VERSION 5.8 ;
BUSBITCHARS "[]" ;
DIVIDERCHAR "/" ;
UNITS
    DATABASE MICRONS 1000 ;
END UNITS

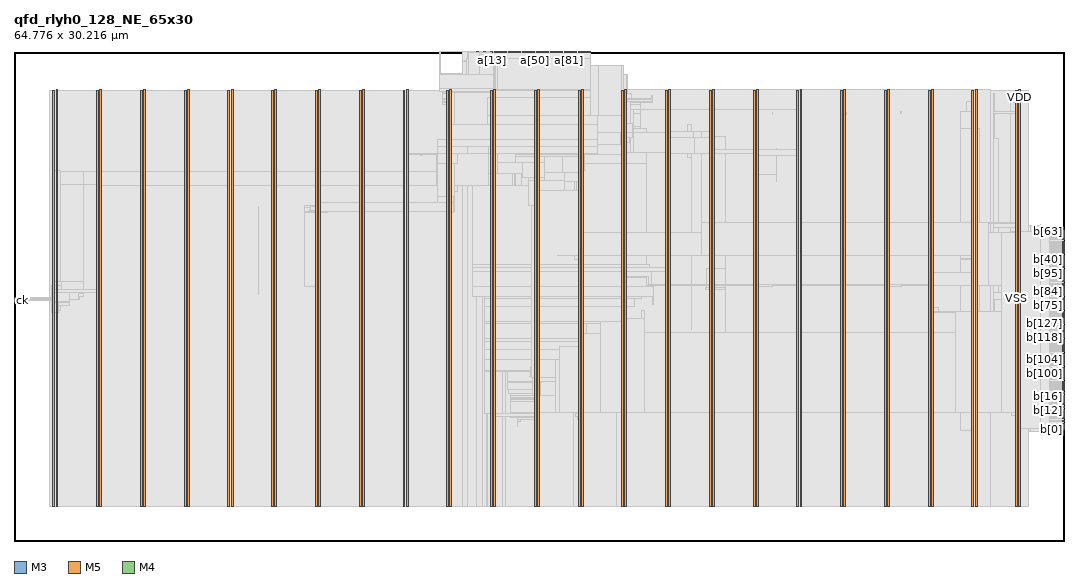
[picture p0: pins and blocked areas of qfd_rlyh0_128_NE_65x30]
MACRO qfd_rlyh0_128_NE_65x30
  FOREIGN qfd_rlyh0_128_NE_65x30 0 0 ;
  CLASS BLOCK ;
  SIZE 64.776 BY 30.216 ;
  PIN a[0]
    DIRECTION INPUT ;
    USE SIGNAL ;
    PORT
      LAYER M3 ;
        RECT  28.548 30.179 28.566 30.216 ;
    END
  END a[0]
  PIN a[100]
    DIRECTION INPUT ;
    USE SIGNAL ;
    PORT
      LAYER M5 ;
        RECT  29.904 30.132 29.928 30.216 ;
    END
  END a[100]
  PIN a[101]
    DIRECTION INPUT ;
    USE SIGNAL ;
    PORT
      LAYER M5 ;
        RECT  30 30.132 30.024 30.216 ;
    END
  END a[101]
  PIN a[102]
    DIRECTION INPUT ;
    USE SIGNAL ;
    PORT
      LAYER M5 ;
        RECT  30.096 30.132 30.12 30.216 ;
    END
  END a[102]
  PIN a[103]
    DIRECTION INPUT ;
    USE SIGNAL ;
    PORT
      LAYER M5 ;
        RECT  30.192 30.132 30.216 30.216 ;
    END
  END a[103]
  PIN a[104]
    DIRECTION INPUT ;
    USE SIGNAL ;
    PORT
      LAYER M5 ;
        RECT  30.288 30.132 30.312 30.216 ;
    END
  END a[104]
  PIN a[105]
    DIRECTION INPUT ;
    USE SIGNAL ;
    PORT
      LAYER M5 ;
        RECT  30.384 30.132 30.408 30.216 ;
    END
  END a[105]
  PIN a[106]
    DIRECTION INPUT ;
    USE SIGNAL ;
    PORT
      LAYER M5 ;
        RECT  30.48 30.132 30.504 30.216 ;
    END
  END a[106]
  PIN a[107]
    DIRECTION INPUT ;
    USE SIGNAL ;
    PORT
      LAYER M5 ;
        RECT  30.576 30.132 30.6 30.216 ;
    END
  END a[107]
  PIN a[108]
    DIRECTION INPUT ;
    USE SIGNAL ;
    PORT
      LAYER M5 ;
        RECT  30.672 30.132 30.696 30.216 ;
    END
  END a[108]
  PIN a[109]
    DIRECTION INPUT ;
    USE SIGNAL ;
    PORT
      LAYER M5 ;
        RECT  30.768 30.132 30.792 30.216 ;
    END
  END a[109]
  PIN a[10]
    DIRECTION INPUT ;
    USE SIGNAL ;
    PORT
      LAYER M3 ;
        RECT  29.268 30.179 29.286 30.216 ;
    END
  END a[10]
  PIN a[110]
    DIRECTION INPUT ;
    USE SIGNAL ;
    PORT
      LAYER M5 ;
        RECT  30.864 30.132 30.888 30.216 ;
    END
  END a[110]
  PIN a[111]
    DIRECTION INPUT ;
    USE SIGNAL ;
    PORT
      LAYER M5 ;
        RECT  30.96 30.132 30.984 30.216 ;
    END
  END a[111]
  PIN a[112]
    DIRECTION INPUT ;
    USE SIGNAL ;
    PORT
      LAYER M5 ;
        RECT  31.056 30.132 31.08 30.216 ;
    END
  END a[112]
  PIN a[113]
    DIRECTION INPUT ;
    USE SIGNAL ;
    PORT
      LAYER M5 ;
        RECT  31.152 30.132 31.176 30.216 ;
    END
  END a[113]
  PIN a[114]
    DIRECTION INPUT ;
    USE SIGNAL ;
    PORT
      LAYER M5 ;
        RECT  31.248 30.132 31.272 30.216 ;
    END
  END a[114]
  PIN a[115]
    DIRECTION INPUT ;
    USE SIGNAL ;
    PORT
      LAYER M5 ;
        RECT  31.344 30.132 31.368 30.216 ;
    END
  END a[115]
  PIN a[116]
    DIRECTION INPUT ;
    USE SIGNAL ;
    PORT
      LAYER M5 ;
        RECT  31.44 30.132 31.464 30.216 ;
    END
  END a[116]
  PIN a[117]
    DIRECTION INPUT ;
    USE SIGNAL ;
    PORT
      LAYER M5 ;
        RECT  31.536 30.132 31.56 30.216 ;
    END
  END a[117]
  PIN a[118]
    DIRECTION INPUT ;
    USE SIGNAL ;
    PORT
      LAYER M5 ;
        RECT  31.632 30.132 31.656 30.216 ;
    END
  END a[118]
  PIN a[119]
    DIRECTION INPUT ;
    USE SIGNAL ;
    PORT
      LAYER M5 ;
        RECT  31.728 30.132 31.752 30.216 ;
    END
  END a[119]
  PIN a[11]
    DIRECTION INPUT ;
    USE SIGNAL ;
    PORT
      LAYER M3 ;
        RECT  29.34 30.179 29.358 30.216 ;
    END
  END a[11]
  PIN a[120]
    DIRECTION INPUT ;
    USE SIGNAL ;
    PORT
      LAYER M5 ;
        RECT  31.824 30.132 31.848 30.216 ;
    END
  END a[120]
  PIN a[121]
    DIRECTION INPUT ;
    USE SIGNAL ;
    PORT
      LAYER M5 ;
        RECT  31.92 30.132 31.944 30.216 ;
    END
  END a[121]
  PIN a[122]
    DIRECTION INPUT ;
    USE SIGNAL ;
    PORT
      LAYER M5 ;
        RECT  32.016 30.132 32.04 30.216 ;
    END
  END a[122]
  PIN a[123]
    DIRECTION INPUT ;
    USE SIGNAL ;
    PORT
      LAYER M5 ;
        RECT  32.112 30.132 32.136 30.216 ;
    END
  END a[123]
  PIN a[124]
    DIRECTION INPUT ;
    USE SIGNAL ;
    PORT
      LAYER M5 ;
        RECT  32.208 30.132 32.232 30.216 ;
    END
  END a[124]
  PIN a[125]
    DIRECTION INPUT ;
    USE SIGNAL ;
    PORT
      LAYER M5 ;
        RECT  32.304 30.132 32.328 30.216 ;
    END
  END a[125]
  PIN a[126]
    DIRECTION INPUT ;
    USE SIGNAL ;
    PORT
      LAYER M5 ;
        RECT  32.4 30.132 32.424 30.216 ;
    END
  END a[126]
  PIN a[127]
    DIRECTION INPUT ;
    USE SIGNAL ;
    PORT
      LAYER M5 ;
        RECT  32.496 30.132 32.52 30.216 ;
    END
  END a[127]
  PIN a[12]
    DIRECTION INPUT ;
    USE SIGNAL ;
    PORT
      LAYER M3 ;
        RECT  29.412 30.179 29.43 30.216 ;
    END
  END a[12]
  PIN a[13]
    DIRECTION INPUT ;
    USE SIGNAL ;
    PORT
      LAYER M3 ;
        RECT  29.484 30.179 29.502 30.216 ;
    END
  END a[13]
  PIN a[14]
    DIRECTION INPUT ;
    USE SIGNAL ;
    PORT
      LAYER M3 ;
        RECT  29.556 30.179 29.574 30.216 ;
    END
  END a[14]
  PIN a[15]
    DIRECTION INPUT ;
    USE SIGNAL ;
    PORT
      LAYER M3 ;
        RECT  29.628 30.179 29.646 30.216 ;
    END
  END a[15]
  PIN a[16]
    DIRECTION INPUT ;
    USE SIGNAL ;
    PORT
      LAYER M3 ;
        RECT  29.7 30.179 29.718 30.216 ;
    END
  END a[16]
  PIN a[17]
    DIRECTION INPUT ;
    USE SIGNAL ;
    PORT
      LAYER M3 ;
        RECT  29.772 30.179 29.79 30.216 ;
    END
  END a[17]
  PIN a[18]
    DIRECTION INPUT ;
    USE SIGNAL ;
    PORT
      LAYER M3 ;
        RECT  29.844 30.179 29.862 30.216 ;
    END
  END a[18]
  PIN a[19]
    DIRECTION INPUT ;
    USE SIGNAL ;
    PORT
      LAYER M3 ;
        RECT  29.916 30.179 29.934 30.216 ;
    END
  END a[19]
  PIN a[1]
    DIRECTION INPUT ;
    USE SIGNAL ;
    PORT
      LAYER M3 ;
        RECT  28.62 30.179 28.638 30.216 ;
    END
  END a[1]
  PIN a[20]
    DIRECTION INPUT ;
    USE SIGNAL ;
    PORT
      LAYER M3 ;
        RECT  29.988 30.179 30.006 30.216 ;
    END
  END a[20]
  PIN a[21]
    DIRECTION INPUT ;
    USE SIGNAL ;
    PORT
      LAYER M3 ;
        RECT  30.06 30.179 30.078 30.216 ;
    END
  END a[21]
  PIN a[22]
    DIRECTION INPUT ;
    USE SIGNAL ;
    PORT
      LAYER M3 ;
        RECT  30.132 30.179 30.15 30.216 ;
    END
  END a[22]
  PIN a[23]
    DIRECTION INPUT ;
    USE SIGNAL ;
    PORT
      LAYER M3 ;
        RECT  30.204 30.179 30.222 30.216 ;
    END
  END a[23]
  PIN a[24]
    DIRECTION INPUT ;
    USE SIGNAL ;
    PORT
      LAYER M3 ;
        RECT  30.276 30.179 30.294 30.216 ;
    END
  END a[24]
  PIN a[25]
    DIRECTION INPUT ;
    USE SIGNAL ;
    PORT
      LAYER M3 ;
        RECT  30.348 30.179 30.366 30.216 ;
    END
  END a[25]
  PIN a[26]
    DIRECTION INPUT ;
    USE SIGNAL ;
    PORT
      LAYER M3 ;
        RECT  30.42 30.179 30.438 30.216 ;
    END
  END a[26]
  PIN a[27]
    DIRECTION INPUT ;
    USE SIGNAL ;
    PORT
      LAYER M3 ;
        RECT  30.492 30.179 30.51 30.216 ;
    END
  END a[27]
  PIN a[28]
    DIRECTION INPUT ;
    USE SIGNAL ;
    PORT
      LAYER M3 ;
        RECT  30.564 30.179 30.582 30.216 ;
    END
  END a[28]
  PIN a[29]
    DIRECTION INPUT ;
    USE SIGNAL ;
    PORT
      LAYER M3 ;
        RECT  30.636 30.179 30.654 30.216 ;
    END
  END a[29]
  PIN a[2]
    DIRECTION INPUT ;
    USE SIGNAL ;
    PORT
      LAYER M3 ;
        RECT  28.692 30.179 28.71 30.216 ;
    END
  END a[2]
  PIN a[30]
    DIRECTION INPUT ;
    USE SIGNAL ;
    PORT
      LAYER M3 ;
        RECT  30.708 30.179 30.726 30.216 ;
    END
  END a[30]
  PIN a[31]
    DIRECTION INPUT ;
    USE SIGNAL ;
    PORT
      LAYER M3 ;
        RECT  30.78 30.179 30.798 30.216 ;
    END
  END a[31]
  PIN a[32]
    DIRECTION INPUT ;
    USE SIGNAL ;
    PORT
      LAYER M3 ;
        RECT  30.852 30.179 30.87 30.216 ;
    END
  END a[32]
  PIN a[33]
    DIRECTION INPUT ;
    USE SIGNAL ;
    PORT
      LAYER M3 ;
        RECT  30.924 30.179 30.942 30.216 ;
    END
  END a[33]
  PIN a[34]
    DIRECTION INPUT ;
    USE SIGNAL ;
    PORT
      LAYER M3 ;
        RECT  30.996 30.179 31.014 30.216 ;
    END
  END a[34]
  PIN a[35]
    DIRECTION INPUT ;
    USE SIGNAL ;
    PORT
      LAYER M3 ;
        RECT  31.068 30.179 31.086 30.216 ;
    END
  END a[35]
  PIN a[36]
    DIRECTION INPUT ;
    USE SIGNAL ;
    PORT
      LAYER M3 ;
        RECT  31.14 30.179 31.158 30.216 ;
    END
  END a[36]
  PIN a[37]
    DIRECTION INPUT ;
    USE SIGNAL ;
    PORT
      LAYER M3 ;
        RECT  31.212 30.179 31.23 30.216 ;
    END
  END a[37]
  PIN a[38]
    DIRECTION INPUT ;
    USE SIGNAL ;
    PORT
      LAYER M3 ;
        RECT  31.284 30.179 31.302 30.216 ;
    END
  END a[38]
  PIN a[39]
    DIRECTION INPUT ;
    USE SIGNAL ;
    PORT
      LAYER M3 ;
        RECT  31.356 30.179 31.374 30.216 ;
    END
  END a[39]
  PIN a[3]
    DIRECTION INPUT ;
    USE SIGNAL ;
    PORT
      LAYER M3 ;
        RECT  28.764 30.179 28.782 30.216 ;
    END
  END a[3]
  PIN a[40]
    DIRECTION INPUT ;
    USE SIGNAL ;
    PORT
      LAYER M3 ;
        RECT  31.428 30.179 31.446 30.216 ;
    END
  END a[40]
  PIN a[41]
    DIRECTION INPUT ;
    USE SIGNAL ;
    PORT
      LAYER M3 ;
        RECT  31.5 30.179 31.518 30.216 ;
    END
  END a[41]
  PIN a[42]
    DIRECTION INPUT ;
    USE SIGNAL ;
    PORT
      LAYER M3 ;
        RECT  31.572 30.179 31.59 30.216 ;
    END
  END a[42]
  PIN a[43]
    DIRECTION INPUT ;
    USE SIGNAL ;
    PORT
      LAYER M3 ;
        RECT  31.644 30.179 31.662 30.216 ;
    END
  END a[43]
  PIN a[44]
    DIRECTION INPUT ;
    USE SIGNAL ;
    PORT
      LAYER M3 ;
        RECT  31.716 30.179 31.734 30.216 ;
    END
  END a[44]
  PIN a[45]
    DIRECTION INPUT ;
    USE SIGNAL ;
    PORT
      LAYER M3 ;
        RECT  31.788 30.179 31.806 30.216 ;
    END
  END a[45]
  PIN a[46]
    DIRECTION INPUT ;
    USE SIGNAL ;
    PORT
      LAYER M3 ;
        RECT  31.86 30.179 31.878 30.216 ;
    END
  END a[46]
  PIN a[47]
    DIRECTION INPUT ;
    USE SIGNAL ;
    PORT
      LAYER M3 ;
        RECT  31.932 30.179 31.95 30.216 ;
    END
  END a[47]
  PIN a[48]
    DIRECTION INPUT ;
    USE SIGNAL ;
    PORT
      LAYER M3 ;
        RECT  32.004 30.179 32.022 30.216 ;
    END
  END a[48]
  PIN a[49]
    DIRECTION INPUT ;
    USE SIGNAL ;
    PORT
      LAYER M3 ;
        RECT  32.076 30.179 32.094 30.216 ;
    END
  END a[49]
  PIN a[4]
    DIRECTION INPUT ;
    USE SIGNAL ;
    PORT
      LAYER M3 ;
        RECT  28.836 30.179 28.854 30.216 ;
    END
  END a[4]
  PIN a[50]
    DIRECTION INPUT ;
    USE SIGNAL ;
    PORT
      LAYER M3 ;
        RECT  32.148 30.179 32.166 30.216 ;
    END
  END a[50]
  PIN a[51]
    DIRECTION INPUT ;
    USE SIGNAL ;
    PORT
      LAYER M3 ;
        RECT  32.22 30.179 32.238 30.216 ;
    END
  END a[51]
  PIN a[52]
    DIRECTION INPUT ;
    USE SIGNAL ;
    PORT
      LAYER M3 ;
        RECT  32.292 30.179 32.31 30.216 ;
    END
  END a[52]
  PIN a[53]
    DIRECTION INPUT ;
    USE SIGNAL ;
    PORT
      LAYER M3 ;
        RECT  32.364 30.179 32.382 30.216 ;
    END
  END a[53]
  PIN a[54]
    DIRECTION INPUT ;
    USE SIGNAL ;
    PORT
      LAYER M3 ;
        RECT  32.436 30.179 32.454 30.216 ;
    END
  END a[54]
  PIN a[55]
    DIRECTION INPUT ;
    USE SIGNAL ;
    PORT
      LAYER M3 ;
        RECT  32.508 30.179 32.526 30.216 ;
    END
  END a[55]
  PIN a[56]
    DIRECTION INPUT ;
    USE SIGNAL ;
    PORT
      LAYER M3 ;
        RECT  32.58 30.179 32.598 30.216 ;
    END
  END a[56]
  PIN a[57]
    DIRECTION INPUT ;
    USE SIGNAL ;
    PORT
      LAYER M3 ;
        RECT  32.652 30.179 32.67 30.216 ;
    END
  END a[57]
  PIN a[58]
    DIRECTION INPUT ;
    USE SIGNAL ;
    PORT
      LAYER M3 ;
        RECT  32.724 30.179 32.742 30.216 ;
    END
  END a[58]
  PIN a[59]
    DIRECTION INPUT ;
    USE SIGNAL ;
    PORT
      LAYER M3 ;
        RECT  32.796 30.179 32.814 30.216 ;
    END
  END a[59]
  PIN a[5]
    DIRECTION INPUT ;
    USE SIGNAL ;
    PORT
      LAYER M3 ;
        RECT  28.908 30.179 28.926 30.216 ;
    END
  END a[5]
  PIN a[60]
    DIRECTION INPUT ;
    USE SIGNAL ;
    PORT
      LAYER M3 ;
        RECT  32.868 30.179 32.886 30.216 ;
    END
  END a[60]
  PIN a[61]
    DIRECTION INPUT ;
    USE SIGNAL ;
    PORT
      LAYER M3 ;
        RECT  32.94 30.179 32.958 30.216 ;
    END
  END a[61]
  PIN a[62]
    DIRECTION INPUT ;
    USE SIGNAL ;
    PORT
      LAYER M3 ;
        RECT  33.012 30.179 33.03 30.216 ;
    END
  END a[62]
  PIN a[63]
    DIRECTION INPUT ;
    USE SIGNAL ;
    PORT
      LAYER M3 ;
        RECT  33.084 30.179 33.102 30.216 ;
    END
  END a[63]
  PIN a[64]
    DIRECTION INPUT ;
    USE SIGNAL ;
    PORT
      LAYER M5 ;
        RECT  32.592 30.132 32.616 30.216 ;
    END
  END a[64]
  PIN a[65]
    DIRECTION INPUT ;
    USE SIGNAL ;
    PORT
      LAYER M5 ;
        RECT  32.688 30.132 32.712 30.216 ;
    END
  END a[65]
  PIN a[66]
    DIRECTION INPUT ;
    USE SIGNAL ;
    PORT
      LAYER M5 ;
        RECT  32.784 30.132 32.808 30.216 ;
    END
  END a[66]
  PIN a[67]
    DIRECTION INPUT ;
    USE SIGNAL ;
    PORT
      LAYER M5 ;
        RECT  32.88 30.132 32.904 30.216 ;
    END
  END a[67]
  PIN a[68]
    DIRECTION INPUT ;
    USE SIGNAL ;
    PORT
      LAYER M5 ;
        RECT  32.976 30.132 33 30.216 ;
    END
  END a[68]
  PIN a[69]
    DIRECTION INPUT ;
    USE SIGNAL ;
    PORT
      LAYER M5 ;
        RECT  33.072 30.132 33.096 30.216 ;
    END
  END a[69]
  PIN a[6]
    DIRECTION INPUT ;
    USE SIGNAL ;
    PORT
      LAYER M3 ;
        RECT  28.98 30.179 28.998 30.216 ;
    END
  END a[6]
  PIN a[70]
    DIRECTION INPUT ;
    USE SIGNAL ;
    PORT
      LAYER M5 ;
        RECT  33.168 30.132 33.192 30.216 ;
    END
  END a[70]
  PIN a[71]
    DIRECTION INPUT ;
    USE SIGNAL ;
    PORT
      LAYER M5 ;
        RECT  33.264 30.132 33.288 30.216 ;
    END
  END a[71]
  PIN a[72]
    DIRECTION INPUT ;
    USE SIGNAL ;
    PORT
      LAYER M5 ;
        RECT  33.36 30.132 33.384 30.216 ;
    END
  END a[72]
  PIN a[73]
    DIRECTION INPUT ;
    USE SIGNAL ;
    PORT
      LAYER M5 ;
        RECT  33.456 30.132 33.48 30.216 ;
    END
  END a[73]
  PIN a[74]
    DIRECTION INPUT ;
    USE SIGNAL ;
    PORT
      LAYER M5 ;
        RECT  33.552 30.132 33.576 30.216 ;
    END
  END a[74]
  PIN a[75]
    DIRECTION INPUT ;
    USE SIGNAL ;
    PORT
      LAYER M5 ;
        RECT  33.648 30.132 33.672 30.216 ;
    END
  END a[75]
  PIN a[76]
    DIRECTION INPUT ;
    USE SIGNAL ;
    PORT
      LAYER M5 ;
        RECT  33.744 30.132 33.768 30.216 ;
    END
  END a[76]
  PIN a[77]
    DIRECTION INPUT ;
    USE SIGNAL ;
    PORT
      LAYER M5 ;
        RECT  33.84 30.132 33.864 30.216 ;
    END
  END a[77]
  PIN a[78]
    DIRECTION INPUT ;
    USE SIGNAL ;
    PORT
      LAYER M5 ;
        RECT  33.936 30.132 33.96 30.216 ;
    END
  END a[78]
  PIN a[79]
    DIRECTION INPUT ;
    USE SIGNAL ;
    PORT
      LAYER M5 ;
        RECT  34.032 30.132 34.056 30.216 ;
    END
  END a[79]
  PIN a[7]
    DIRECTION INPUT ;
    USE SIGNAL ;
    PORT
      LAYER M3 ;
        RECT  29.052 30.179 29.07 30.216 ;
    END
  END a[7]
  PIN a[80]
    DIRECTION INPUT ;
    USE SIGNAL ;
    PORT
      LAYER M5 ;
        RECT  34.128 30.132 34.152 30.216 ;
    END
  END a[80]
  PIN a[81]
    DIRECTION INPUT ;
    USE SIGNAL ;
    PORT
      LAYER M5 ;
        RECT  34.224 30.132 34.248 30.216 ;
    END
  END a[81]
  PIN a[82]
    DIRECTION INPUT ;
    USE SIGNAL ;
    PORT
      LAYER M5 ;
        RECT  34.32 30.132 34.344 30.216 ;
    END
  END a[82]
  PIN a[83]
    DIRECTION INPUT ;
    USE SIGNAL ;
    PORT
      LAYER M5 ;
        RECT  34.416 30.132 34.44 30.216 ;
    END
  END a[83]
  PIN a[84]
    DIRECTION INPUT ;
    USE SIGNAL ;
    PORT
      LAYER M5 ;
        RECT  34.512 30.132 34.536 30.216 ;
    END
  END a[84]
  PIN a[85]
    DIRECTION INPUT ;
    USE SIGNAL ;
    PORT
      LAYER M5 ;
        RECT  34.608 30.132 34.632 30.216 ;
    END
  END a[85]
  PIN a[86]
    DIRECTION INPUT ;
    USE SIGNAL ;
    PORT
      LAYER M5 ;
        RECT  34.704 30.132 34.728 30.216 ;
    END
  END a[86]
  PIN a[87]
    DIRECTION INPUT ;
    USE SIGNAL ;
    PORT
      LAYER M5 ;
        RECT  34.8 30.132 34.824 30.216 ;
    END
  END a[87]
  PIN a[88]
    DIRECTION INPUT ;
    USE SIGNAL ;
    PORT
      LAYER M5 ;
        RECT  34.896 30.132 34.92 30.216 ;
    END
  END a[88]
  PIN a[89]
    DIRECTION INPUT ;
    USE SIGNAL ;
    PORT
      LAYER M5 ;
        RECT  34.992 30.132 35.016 30.216 ;
    END
  END a[89]
  PIN a[8]
    DIRECTION INPUT ;
    USE SIGNAL ;
    PORT
      LAYER M3 ;
        RECT  29.124 30.179 29.142 30.216 ;
    END
  END a[8]
  PIN a[90]
    DIRECTION INPUT ;
    USE SIGNAL ;
    PORT
      LAYER M5 ;
        RECT  35.088 30.132 35.112 30.216 ;
    END
  END a[90]
  PIN a[91]
    DIRECTION INPUT ;
    USE SIGNAL ;
    PORT
      LAYER M5 ;
        RECT  35.184 30.132 35.208 30.216 ;
    END
  END a[91]
  PIN a[92]
    DIRECTION INPUT ;
    USE SIGNAL ;
    PORT
      LAYER M5 ;
        RECT  35.28 30.132 35.304 30.216 ;
    END
  END a[92]
  PIN a[93]
    DIRECTION INPUT ;
    USE SIGNAL ;
    PORT
      LAYER M5 ;
        RECT  35.376 30.132 35.4 30.216 ;
    END
  END a[93]
  PIN a[94]
    DIRECTION INPUT ;
    USE SIGNAL ;
    PORT
      LAYER M5 ;
        RECT  35.472 30.132 35.496 30.216 ;
    END
  END a[94]
  PIN a[95]
    DIRECTION INPUT ;
    USE SIGNAL ;
    PORT
      LAYER M5 ;
        RECT  35.568 30.132 35.592 30.216 ;
    END
  END a[95]
  PIN a[96]
    DIRECTION INPUT ;
    USE SIGNAL ;
    PORT
      LAYER M5 ;
        RECT  29.52 30.132 29.544 30.216 ;
    END
  END a[96]
  PIN a[97]
    DIRECTION INPUT ;
    USE SIGNAL ;
    PORT
      LAYER M5 ;
        RECT  29.616 30.132 29.64 30.216 ;
    END
  END a[97]
  PIN a[98]
    DIRECTION INPUT ;
    USE SIGNAL ;
    PORT
      LAYER M5 ;
        RECT  29.712 30.132 29.736 30.216 ;
    END
  END a[98]
  PIN a[99]
    DIRECTION INPUT ;
    USE SIGNAL ;
    PORT
      LAYER M5 ;
        RECT  29.808 30.132 29.832 30.216 ;
    END
  END a[99]
  PIN a[9]
    DIRECTION INPUT ;
    USE SIGNAL ;
    PORT
      LAYER M3 ;
        RECT  29.196 30.179 29.214 30.216 ;
    END
  END a[9]
  PIN b[0]
    DIRECTION OUTPUT ;
    USE SIGNAL ;
    PORT
      LAYER M4 ;
        RECT  64.692 6.864 64.776 6.888 ;
    END
  END b[0]
  PIN b[100]
    DIRECTION OUTPUT ;
    USE SIGNAL ;
    PORT
      LAYER M4 ;
        RECT  64.692 10.32 64.776 10.344 ;
    END
  END b[100]
  PIN b[101]
    DIRECTION OUTPUT ;
    USE SIGNAL ;
    PORT
      LAYER M4 ;
        RECT  64.692 10.416 64.776 10.44 ;
    END
  END b[101]
  PIN b[102]
    DIRECTION OUTPUT ;
    USE SIGNAL ;
    PORT
      LAYER M4 ;
        RECT  64.692 10.512 64.776 10.536 ;
    END
  END b[102]
  PIN b[103]
    DIRECTION OUTPUT ;
    USE SIGNAL ;
    PORT
      LAYER M4 ;
        RECT  64.692 10.608 64.776 10.632 ;
    END
  END b[103]
  PIN b[104]
    DIRECTION OUTPUT ;
    USE SIGNAL ;
    PORT
      LAYER M4 ;
        RECT  64.692 10.704 64.776 10.728 ;
    END
  END b[104]
  PIN b[105]
    DIRECTION OUTPUT ;
    USE SIGNAL ;
    PORT
      LAYER M4 ;
        RECT  64.692 10.8 64.776 10.824 ;
    END
  END b[105]
  PIN b[106]
    DIRECTION OUTPUT ;
    USE SIGNAL ;
    PORT
      LAYER M4 ;
        RECT  64.692 10.896 64.776 10.92 ;
    END
  END b[106]
  PIN b[107]
    DIRECTION OUTPUT ;
    USE SIGNAL ;
    PORT
      LAYER M4 ;
        RECT  64.692 10.992 64.776 11.016 ;
    END
  END b[107]
  PIN b[108]
    DIRECTION OUTPUT ;
    USE SIGNAL ;
    PORT
      LAYER M4 ;
        RECT  64.692 11.088 64.776 11.112 ;
    END
  END b[108]
  PIN b[109]
    DIRECTION OUTPUT ;
    USE SIGNAL ;
    PORT
      LAYER M4 ;
        RECT  64.692 11.184 64.776 11.208 ;
    END
  END b[109]
  PIN b[10]
    DIRECTION OUTPUT ;
    USE SIGNAL ;
    PORT
      LAYER M4 ;
        RECT  64.692 7.824 64.776 7.848 ;
    END
  END b[10]
  PIN b[110]
    DIRECTION OUTPUT ;
    USE SIGNAL ;
    PORT
      LAYER M4 ;
        RECT  64.692 11.28 64.776 11.304 ;
    END
  END b[110]
  PIN b[111]
    DIRECTION OUTPUT ;
    USE SIGNAL ;
    PORT
      LAYER M4 ;
        RECT  64.692 11.376 64.776 11.4 ;
    END
  END b[111]
  PIN b[112]
    DIRECTION OUTPUT ;
    USE SIGNAL ;
    PORT
      LAYER M4 ;
        RECT  64.692 11.472 64.776 11.496 ;
    END
  END b[112]
  PIN b[113]
    DIRECTION OUTPUT ;
    USE SIGNAL ;
    PORT
      LAYER M4 ;
        RECT  64.692 11.568 64.776 11.592 ;
    END
  END b[113]
  PIN b[114]
    DIRECTION OUTPUT ;
    USE SIGNAL ;
    PORT
      LAYER M4 ;
        RECT  64.692 11.664 64.776 11.688 ;
    END
  END b[114]
  PIN b[115]
    DIRECTION OUTPUT ;
    USE SIGNAL ;
    PORT
      LAYER M4 ;
        RECT  64.692 11.76 64.776 11.784 ;
    END
  END b[115]
  PIN b[116]
    DIRECTION OUTPUT ;
    USE SIGNAL ;
    PORT
      LAYER M4 ;
        RECT  64.692 11.856 64.776 11.88 ;
    END
  END b[116]
  PIN b[117]
    DIRECTION OUTPUT ;
    USE SIGNAL ;
    PORT
      LAYER M4 ;
        RECT  64.692 11.952 64.776 11.976 ;
    END
  END b[117]
  PIN b[118]
    DIRECTION OUTPUT ;
    USE SIGNAL ;
    PORT
      LAYER M4 ;
        RECT  64.692 12.048 64.776 12.072 ;
    END
  END b[118]
  PIN b[119]
    DIRECTION OUTPUT ;
    USE SIGNAL ;
    PORT
      LAYER M4 ;
        RECT  64.692 12.144 64.776 12.168 ;
    END
  END b[119]
  PIN b[11]
    DIRECTION OUTPUT ;
    USE SIGNAL ;
    PORT
      LAYER M4 ;
        RECT  64.692 7.92 64.776 7.944 ;
    END
  END b[11]
  PIN b[120]
    DIRECTION OUTPUT ;
    USE SIGNAL ;
    PORT
      LAYER M4 ;
        RECT  64.692 12.24 64.776 12.264 ;
    END
  END b[120]
  PIN b[121]
    DIRECTION OUTPUT ;
    USE SIGNAL ;
    PORT
      LAYER M4 ;
        RECT  64.692 12.336 64.776 12.36 ;
    END
  END b[121]
  PIN b[122]
    DIRECTION OUTPUT ;
    USE SIGNAL ;
    PORT
      LAYER M4 ;
        RECT  64.692 12.432 64.776 12.456 ;
    END
  END b[122]
  PIN b[123]
    DIRECTION OUTPUT ;
    USE SIGNAL ;
    PORT
      LAYER M4 ;
        RECT  64.692 12.528 64.776 12.552 ;
    END
  END b[123]
  PIN b[124]
    DIRECTION OUTPUT ;
    USE SIGNAL ;
    PORT
      LAYER M4 ;
        RECT  64.692 12.624 64.776 12.648 ;
    END
  END b[124]
  PIN b[125]
    DIRECTION OUTPUT ;
    USE SIGNAL ;
    PORT
      LAYER M4 ;
        RECT  64.692 12.72 64.776 12.744 ;
    END
  END b[125]
  PIN b[126]
    DIRECTION OUTPUT ;
    USE SIGNAL ;
    PORT
      LAYER M4 ;
        RECT  64.692 12.816 64.776 12.84 ;
    END
  END b[126]
  PIN b[127]
    DIRECTION OUTPUT ;
    USE SIGNAL ;
    PORT
      LAYER M4 ;
        RECT  64.692 12.912 64.776 12.936 ;
    END
  END b[127]
  PIN b[12]
    DIRECTION OUTPUT ;
    USE SIGNAL ;
    PORT
      LAYER M4 ;
        RECT  64.692 8.016 64.776 8.04 ;
    END
  END b[12]
  PIN b[13]
    DIRECTION OUTPUT ;
    USE SIGNAL ;
    PORT
      LAYER M4 ;
        RECT  64.692 8.112 64.776 8.136 ;
    END
  END b[13]
  PIN b[14]
    DIRECTION OUTPUT ;
    USE SIGNAL ;
    PORT
      LAYER M4 ;
        RECT  64.692 8.208 64.776 8.232 ;
    END
  END b[14]
  PIN b[15]
    DIRECTION OUTPUT ;
    USE SIGNAL ;
    PORT
      LAYER M4 ;
        RECT  64.692 8.304 64.776 8.328 ;
    END
  END b[15]
  PIN b[16]
    DIRECTION OUTPUT ;
    USE SIGNAL ;
    PORT
      LAYER M4 ;
        RECT  64.692 8.4 64.776 8.424 ;
    END
  END b[16]
  PIN b[17]
    DIRECTION OUTPUT ;
    USE SIGNAL ;
    PORT
      LAYER M4 ;
        RECT  64.692 8.496 64.776 8.52 ;
    END
  END b[17]
  PIN b[18]
    DIRECTION OUTPUT ;
    USE SIGNAL ;
    PORT
      LAYER M4 ;
        RECT  64.692 8.592 64.776 8.616 ;
    END
  END b[18]
  PIN b[19]
    DIRECTION OUTPUT ;
    USE SIGNAL ;
    PORT
      LAYER M4 ;
        RECT  64.692 8.688 64.776 8.712 ;
    END
  END b[19]
  PIN b[1]
    DIRECTION OUTPUT ;
    USE SIGNAL ;
    PORT
      LAYER M4 ;
        RECT  64.692 6.96 64.776 6.984 ;
    END
  END b[1]
  PIN b[20]
    DIRECTION OUTPUT ;
    USE SIGNAL ;
    PORT
      LAYER M4 ;
        RECT  64.692 8.784 64.776 8.808 ;
    END
  END b[20]
  PIN b[21]
    DIRECTION OUTPUT ;
    USE SIGNAL ;
    PORT
      LAYER M4 ;
        RECT  64.692 8.88 64.776 8.904 ;
    END
  END b[21]
  PIN b[22]
    DIRECTION OUTPUT ;
    USE SIGNAL ;
    PORT
      LAYER M4 ;
        RECT  64.692 8.976 64.776 9 ;
    END
  END b[22]
  PIN b[23]
    DIRECTION OUTPUT ;
    USE SIGNAL ;
    PORT
      LAYER M4 ;
        RECT  64.692 9.072 64.776 9.096 ;
    END
  END b[23]
  PIN b[24]
    DIRECTION OUTPUT ;
    USE SIGNAL ;
    PORT
      LAYER M4 ;
        RECT  64.692 9.168 64.776 9.192 ;
    END
  END b[24]
  PIN b[25]
    DIRECTION OUTPUT ;
    USE SIGNAL ;
    PORT
      LAYER M4 ;
        RECT  64.692 9.264 64.776 9.288 ;
    END
  END b[25]
  PIN b[26]
    DIRECTION OUTPUT ;
    USE SIGNAL ;
    PORT
      LAYER M4 ;
        RECT  64.692 9.36 64.776 9.384 ;
    END
  END b[26]
  PIN b[27]
    DIRECTION OUTPUT ;
    USE SIGNAL ;
    PORT
      LAYER M4 ;
        RECT  64.692 9.456 64.776 9.48 ;
    END
  END b[27]
  PIN b[28]
    DIRECTION OUTPUT ;
    USE SIGNAL ;
    PORT
      LAYER M4 ;
        RECT  64.692 9.552 64.776 9.576 ;
    END
  END b[28]
  PIN b[29]
    DIRECTION OUTPUT ;
    USE SIGNAL ;
    PORT
      LAYER M4 ;
        RECT  64.692 9.648 64.776 9.672 ;
    END
  END b[29]
  PIN b[2]
    DIRECTION OUTPUT ;
    USE SIGNAL ;
    PORT
      LAYER M4 ;
        RECT  64.692 7.056 64.776 7.08 ;
    END
  END b[2]
  PIN b[30]
    DIRECTION OUTPUT ;
    USE SIGNAL ;
    PORT
      LAYER M4 ;
        RECT  64.692 9.744 64.776 9.768 ;
    END
  END b[30]
  PIN b[31]
    DIRECTION OUTPUT ;
    USE SIGNAL ;
    PORT
      LAYER M4 ;
        RECT  64.692 9.84 64.776 9.864 ;
    END
  END b[31]
  PIN b[32]
    DIRECTION OUTPUT ;
    USE SIGNAL ;
    PORT
      LAYER M4 ;
        RECT  64.692 16.08 64.776 16.104 ;
    END
  END b[32]
  PIN b[33]
    DIRECTION OUTPUT ;
    USE SIGNAL ;
    PORT
      LAYER M4 ;
        RECT  64.692 16.176 64.776 16.2 ;
    END
  END b[33]
  PIN b[34]
    DIRECTION OUTPUT ;
    USE SIGNAL ;
    PORT
      LAYER M4 ;
        RECT  64.692 16.272 64.776 16.296 ;
    END
  END b[34]
  PIN b[35]
    DIRECTION OUTPUT ;
    USE SIGNAL ;
    PORT
      LAYER M4 ;
        RECT  64.692 16.368 64.776 16.392 ;
    END
  END b[35]
  PIN b[36]
    DIRECTION OUTPUT ;
    USE SIGNAL ;
    PORT
      LAYER M4 ;
        RECT  64.692 16.464 64.776 16.488 ;
    END
  END b[36]
  PIN b[37]
    DIRECTION OUTPUT ;
    USE SIGNAL ;
    PORT
      LAYER M4 ;
        RECT  64.692 16.56 64.776 16.584 ;
    END
  END b[37]
  PIN b[38]
    DIRECTION OUTPUT ;
    USE SIGNAL ;
    PORT
      LAYER M4 ;
        RECT  64.692 16.656 64.776 16.68 ;
    END
  END b[38]
  PIN b[39]
    DIRECTION OUTPUT ;
    USE SIGNAL ;
    PORT
      LAYER M4 ;
        RECT  64.692 16.752 64.776 16.776 ;
    END
  END b[39]
  PIN b[3]
    DIRECTION OUTPUT ;
    USE SIGNAL ;
    PORT
      LAYER M4 ;
        RECT  64.692 7.152 64.776 7.176 ;
    END
  END b[3]
  PIN b[40]
    DIRECTION OUTPUT ;
    USE SIGNAL ;
    PORT
      LAYER M4 ;
        RECT  64.692 16.848 64.776 16.872 ;
    END
  END b[40]
  PIN b[41]
    DIRECTION OUTPUT ;
    USE SIGNAL ;
    PORT
      LAYER M4 ;
        RECT  64.692 16.944 64.776 16.968 ;
    END
  END b[41]
  PIN b[42]
    DIRECTION OUTPUT ;
    USE SIGNAL ;
    PORT
      LAYER M4 ;
        RECT  64.692 17.04 64.776 17.064 ;
    END
  END b[42]
  PIN b[43]
    DIRECTION OUTPUT ;
    USE SIGNAL ;
    PORT
      LAYER M4 ;
        RECT  64.692 17.136 64.776 17.16 ;
    END
  END b[43]
  PIN b[44]
    DIRECTION OUTPUT ;
    USE SIGNAL ;
    PORT
      LAYER M4 ;
        RECT  64.692 17.232 64.776 17.256 ;
    END
  END b[44]
  PIN b[45]
    DIRECTION OUTPUT ;
    USE SIGNAL ;
    PORT
      LAYER M4 ;
        RECT  64.692 17.328 64.776 17.352 ;
    END
  END b[45]
  PIN b[46]
    DIRECTION OUTPUT ;
    USE SIGNAL ;
    PORT
      LAYER M4 ;
        RECT  64.692 17.424 64.776 17.448 ;
    END
  END b[46]
  PIN b[47]
    DIRECTION OUTPUT ;
    USE SIGNAL ;
    PORT
      LAYER M4 ;
        RECT  64.692 17.52 64.776 17.544 ;
    END
  END b[47]
  PIN b[48]
    DIRECTION OUTPUT ;
    USE SIGNAL ;
    PORT
      LAYER M4 ;
        RECT  64.692 17.616 64.776 17.64 ;
    END
  END b[48]
  PIN b[49]
    DIRECTION OUTPUT ;
    USE SIGNAL ;
    PORT
      LAYER M4 ;
        RECT  64.692 17.712 64.776 17.736 ;
    END
  END b[49]
  PIN b[4]
    DIRECTION OUTPUT ;
    USE SIGNAL ;
    PORT
      LAYER M4 ;
        RECT  64.692 7.248 64.776 7.272 ;
    END
  END b[4]
  PIN b[50]
    DIRECTION OUTPUT ;
    USE SIGNAL ;
    PORT
      LAYER M4 ;
        RECT  64.692 17.808 64.776 17.832 ;
    END
  END b[50]
  PIN b[51]
    DIRECTION OUTPUT ;
    USE SIGNAL ;
    PORT
      LAYER M4 ;
        RECT  64.692 17.904 64.776 17.928 ;
    END
  END b[51]
  PIN b[52]
    DIRECTION OUTPUT ;
    USE SIGNAL ;
    PORT
      LAYER M4 ;
        RECT  64.692 18 64.776 18.024 ;
    END
  END b[52]
  PIN b[53]
    DIRECTION OUTPUT ;
    USE SIGNAL ;
    PORT
      LAYER M4 ;
        RECT  64.692 18.096 64.776 18.12 ;
    END
  END b[53]
  PIN b[54]
    DIRECTION OUTPUT ;
    USE SIGNAL ;
    PORT
      LAYER M4 ;
        RECT  64.692 18.192 64.776 18.216 ;
    END
  END b[54]
  PIN b[55]
    DIRECTION OUTPUT ;
    USE SIGNAL ;
    PORT
      LAYER M4 ;
        RECT  64.692 18.288 64.776 18.312 ;
    END
  END b[55]
  PIN b[56]
    DIRECTION OUTPUT ;
    USE SIGNAL ;
    PORT
      LAYER M4 ;
        RECT  64.692 18.384 64.776 18.408 ;
    END
  END b[56]
  PIN b[57]
    DIRECTION OUTPUT ;
    USE SIGNAL ;
    PORT
      LAYER M4 ;
        RECT  64.692 18.48 64.776 18.504 ;
    END
  END b[57]
  PIN b[58]
    DIRECTION OUTPUT ;
    USE SIGNAL ;
    PORT
      LAYER M4 ;
        RECT  64.692 18.576 64.776 18.6 ;
    END
  END b[58]
  PIN b[59]
    DIRECTION OUTPUT ;
    USE SIGNAL ;
    PORT
      LAYER M4 ;
        RECT  64.692 18.672 64.776 18.696 ;
    END
  END b[59]
  PIN b[5]
    DIRECTION OUTPUT ;
    USE SIGNAL ;
    PORT
      LAYER M4 ;
        RECT  64.692 7.344 64.776 7.368 ;
    END
  END b[5]
  PIN b[60]
    DIRECTION OUTPUT ;
    USE SIGNAL ;
    PORT
      LAYER M4 ;
        RECT  64.692 18.768 64.776 18.792 ;
    END
  END b[60]
  PIN b[61]
    DIRECTION OUTPUT ;
    USE SIGNAL ;
    PORT
      LAYER M4 ;
        RECT  64.692 18.864 64.776 18.888 ;
    END
  END b[61]
  PIN b[62]
    DIRECTION OUTPUT ;
    USE SIGNAL ;
    PORT
      LAYER M4 ;
        RECT  64.692 18.96 64.776 18.984 ;
    END
  END b[62]
  PIN b[63]
    DIRECTION OUTPUT ;
    USE SIGNAL ;
    PORT
      LAYER M4 ;
        RECT  64.692 19.056 64.776 19.08 ;
    END
  END b[63]
  PIN b[64]
    DIRECTION OUTPUT ;
    USE SIGNAL ;
    PORT
      LAYER M4 ;
        RECT  64.692 13.008 64.776 13.032 ;
    END
  END b[64]
  PIN b[65]
    DIRECTION OUTPUT ;
    USE SIGNAL ;
    PORT
      LAYER M4 ;
        RECT  64.692 13.104 64.776 13.128 ;
    END
  END b[65]
  PIN b[66]
    DIRECTION OUTPUT ;
    USE SIGNAL ;
    PORT
      LAYER M4 ;
        RECT  64.692 13.2 64.776 13.224 ;
    END
  END b[66]
  PIN b[67]
    DIRECTION OUTPUT ;
    USE SIGNAL ;
    PORT
      LAYER M4 ;
        RECT  64.692 13.296 64.776 13.32 ;
    END
  END b[67]
  PIN b[68]
    DIRECTION OUTPUT ;
    USE SIGNAL ;
    PORT
      LAYER M4 ;
        RECT  64.692 13.392 64.776 13.416 ;
    END
  END b[68]
  PIN b[69]
    DIRECTION OUTPUT ;
    USE SIGNAL ;
    PORT
      LAYER M4 ;
        RECT  64.692 13.488 64.776 13.512 ;
    END
  END b[69]
  PIN b[6]
    DIRECTION OUTPUT ;
    USE SIGNAL ;
    PORT
      LAYER M4 ;
        RECT  64.692 7.44 64.776 7.464 ;
    END
  END b[6]
  PIN b[70]
    DIRECTION OUTPUT ;
    USE SIGNAL ;
    PORT
      LAYER M4 ;
        RECT  64.692 13.584 64.776 13.608 ;
    END
  END b[70]
  PIN b[71]
    DIRECTION OUTPUT ;
    USE SIGNAL ;
    PORT
      LAYER M4 ;
        RECT  64.692 13.68 64.776 13.704 ;
    END
  END b[71]
  PIN b[72]
    DIRECTION OUTPUT ;
    USE SIGNAL ;
    PORT
      LAYER M4 ;
        RECT  64.692 13.776 64.776 13.8 ;
    END
  END b[72]
  PIN b[73]
    DIRECTION OUTPUT ;
    USE SIGNAL ;
    PORT
      LAYER M4 ;
        RECT  64.692 13.872 64.776 13.896 ;
    END
  END b[73]
  PIN b[74]
    DIRECTION OUTPUT ;
    USE SIGNAL ;
    PORT
      LAYER M4 ;
        RECT  64.692 13.968 64.776 13.992 ;
    END
  END b[74]
  PIN b[75]
    DIRECTION OUTPUT ;
    USE SIGNAL ;
    PORT
      LAYER M4 ;
        RECT  64.692 14.064 64.776 14.088 ;
    END
  END b[75]
  PIN b[76]
    DIRECTION OUTPUT ;
    USE SIGNAL ;
    PORT
      LAYER M4 ;
        RECT  64.692 14.16 64.776 14.184 ;
    END
  END b[76]
  PIN b[77]
    DIRECTION OUTPUT ;
    USE SIGNAL ;
    PORT
      LAYER M4 ;
        RECT  64.692 14.256 64.776 14.28 ;
    END
  END b[77]
  PIN b[78]
    DIRECTION OUTPUT ;
    USE SIGNAL ;
    PORT
      LAYER M4 ;
        RECT  64.692 14.352 64.776 14.376 ;
    END
  END b[78]
  PIN b[79]
    DIRECTION OUTPUT ;
    USE SIGNAL ;
    PORT
      LAYER M4 ;
        RECT  64.692 14.448 64.776 14.472 ;
    END
  END b[79]
  PIN b[7]
    DIRECTION OUTPUT ;
    USE SIGNAL ;
    PORT
      LAYER M4 ;
        RECT  64.692 7.536 64.776 7.56 ;
    END
  END b[7]
  PIN b[80]
    DIRECTION OUTPUT ;
    USE SIGNAL ;
    PORT
      LAYER M4 ;
        RECT  64.692 14.544 64.776 14.568 ;
    END
  END b[80]
  PIN b[81]
    DIRECTION OUTPUT ;
    USE SIGNAL ;
    PORT
      LAYER M4 ;
        RECT  64.692 14.64 64.776 14.664 ;
    END
  END b[81]
  PIN b[82]
    DIRECTION OUTPUT ;
    USE SIGNAL ;
    PORT
      LAYER M4 ;
        RECT  64.692 14.736 64.776 14.76 ;
    END
  END b[82]
  PIN b[83]
    DIRECTION OUTPUT ;
    USE SIGNAL ;
    PORT
      LAYER M4 ;
        RECT  64.692 14.832 64.776 14.856 ;
    END
  END b[83]
  PIN b[84]
    DIRECTION OUTPUT ;
    USE SIGNAL ;
    PORT
      LAYER M4 ;
        RECT  64.692 14.928 64.776 14.952 ;
    END
  END b[84]
  PIN b[85]
    DIRECTION OUTPUT ;
    USE SIGNAL ;
    PORT
      LAYER M4 ;
        RECT  64.692 15.024 64.776 15.048 ;
    END
  END b[85]
  PIN b[86]
    DIRECTION OUTPUT ;
    USE SIGNAL ;
    PORT
      LAYER M4 ;
        RECT  64.692 15.12 64.776 15.144 ;
    END
  END b[86]
  PIN b[87]
    DIRECTION OUTPUT ;
    USE SIGNAL ;
    PORT
      LAYER M4 ;
        RECT  64.692 15.216 64.776 15.24 ;
    END
  END b[87]
  PIN b[88]
    DIRECTION OUTPUT ;
    USE SIGNAL ;
    PORT
      LAYER M4 ;
        RECT  64.692 15.312 64.776 15.336 ;
    END
  END b[88]
  PIN b[89]
    DIRECTION OUTPUT ;
    USE SIGNAL ;
    PORT
      LAYER M4 ;
        RECT  64.692 15.408 64.776 15.432 ;
    END
  END b[89]
  PIN b[8]
    DIRECTION OUTPUT ;
    USE SIGNAL ;
    PORT
      LAYER M4 ;
        RECT  64.692 7.632 64.776 7.656 ;
    END
  END b[8]
  PIN b[90]
    DIRECTION OUTPUT ;
    USE SIGNAL ;
    PORT
      LAYER M4 ;
        RECT  64.692 15.504 64.776 15.528 ;
    END
  END b[90]
  PIN b[91]
    DIRECTION OUTPUT ;
    USE SIGNAL ;
    PORT
      LAYER M4 ;
        RECT  64.692 15.6 64.776 15.624 ;
    END
  END b[91]
  PIN b[92]
    DIRECTION OUTPUT ;
    USE SIGNAL ;
    PORT
      LAYER M4 ;
        RECT  64.692 15.696 64.776 15.72 ;
    END
  END b[92]
  PIN b[93]
    DIRECTION OUTPUT ;
    USE SIGNAL ;
    PORT
      LAYER M4 ;
        RECT  64.692 15.792 64.776 15.816 ;
    END
  END b[93]
  PIN b[94]
    DIRECTION OUTPUT ;
    USE SIGNAL ;
    PORT
      LAYER M4 ;
        RECT  64.692 15.888 64.776 15.912 ;
    END
  END b[94]
  PIN b[95]
    DIRECTION OUTPUT ;
    USE SIGNAL ;
    PORT
      LAYER M4 ;
        RECT  64.692 15.984 64.776 16.008 ;
    END
  END b[95]
  PIN b[96]
    DIRECTION OUTPUT ;
    USE SIGNAL ;
    PORT
      LAYER M4 ;
        RECT  64.692 9.936 64.776 9.96 ;
    END
  END b[96]
  PIN b[97]
    DIRECTION OUTPUT ;
    USE SIGNAL ;
    PORT
      LAYER M4 ;
        RECT  64.692 10.032 64.776 10.056 ;
    END
  END b[97]
  PIN b[98]
    DIRECTION OUTPUT ;
    USE SIGNAL ;
    PORT
      LAYER M4 ;
        RECT  64.692 10.128 64.776 10.152 ;
    END
  END b[98]
  PIN b[99]
    DIRECTION OUTPUT ;
    USE SIGNAL ;
    PORT
      LAYER M4 ;
        RECT  64.692 10.224 64.776 10.248 ;
    END
  END b[99]
  PIN b[9]
    DIRECTION OUTPUT ;
    USE SIGNAL ;
    PORT
      LAYER M4 ;
        RECT  64.692 7.728 64.776 7.752 ;
    END
  END b[9]
  PIN ck
    DIRECTION INPUT ;
    USE SIGNAL ;
    PORT
      LAYER M4 ;
        RECT  0 14.832 0.084 14.856 ;
    END
  END ck
  PIN ck_o
    DIRECTION OUTPUT ;
    USE SIGNAL ;
    PORT
      LAYER M4 ;
        RECT  0 14.928 0.084 14.952 ;
    END
  END ck_o
  PIN eb
    DIRECTION OUTPUT ;
    USE SIGNAL ;
    PORT
      LAYER M4 ;
        RECT  64.692 19.152 64.776 19.176 ;
    END
  END eb
  PIN en
    DIRECTION INPUT ;
    USE SIGNAL ;
    PORT
      LAYER M4 ;
        RECT  0 15.024 0.084 15.048 ;
    END
  END en
  PIN VDD
    DIRECTION INOUT ;
    USE POWER ;
    PORT
      LAYER M5 ;
        RECT  61.992 2.151 62.112 27.833 ;
        RECT  59.292 2.151 59.412 27.833 ;
        RECT  56.592 2.151 56.712 27.833 ;
        RECT  53.892 2.151 54.012 27.833 ;
        RECT  51.192 2.151 51.312 27.833 ;
        RECT  48.492 2.151 48.612 27.833 ;
        RECT  45.792 2.151 45.912 27.833 ;
        RECT  43.092 2.151 43.212 27.833 ;
        RECT  40.392 2.151 40.512 27.833 ;
        RECT  37.692 2.151 37.812 27.833 ;
        RECT  34.992 2.151 35.112 27.833 ;
        RECT  32.292 2.151 32.412 27.833 ;
        RECT  29.592 2.151 29.712 27.833 ;
        RECT  26.892 2.151 27.012 27.833 ;
        RECT  24.192 2.151 24.312 27.833 ;
        RECT  21.492 2.151 21.612 27.833 ;
        RECT  18.792 2.151 18.912 27.833 ;
        RECT  16.092 2.151 16.212 27.833 ;
        RECT  13.392 2.151 13.512 27.833 ;
        RECT  10.692 2.151 10.812 27.833 ;
        RECT  7.992 2.151 8.112 27.833 ;
        RECT  5.292 2.151 5.412 27.833 ;
        RECT  2.592 2.151 2.712 27.833 ;
    END
  END VDD
  PIN VSS
    DIRECTION INOUT ;
    USE GROUND ;
    PORT
      LAYER M5 ;
        RECT  61.8 2.137 61.92 27.819 ;
        RECT  59.1 2.137 59.22 27.819 ;
        RECT  56.4 2.137 56.52 27.819 ;
        RECT  53.7 2.137 53.82 27.819 ;
        RECT  51 2.137 51.12 27.819 ;
        RECT  48.3 2.137 48.42 27.819 ;
        RECT  45.6 2.137 45.72 27.819 ;
        RECT  42.9 2.137 43.02 27.819 ;
        RECT  40.2 2.137 40.32 27.819 ;
        RECT  37.5 2.137 37.62 27.819 ;
        RECT  34.8 2.137 34.92 27.819 ;
        RECT  32.1 2.137 32.22 27.819 ;
        RECT  29.4 2.137 29.52 27.819 ;
        RECT  26.7 2.137 26.82 27.819 ;
        RECT  24 2.137 24.12 27.819 ;
        RECT  21.3 2.137 21.42 27.819 ;
        RECT  18.6 2.137 18.72 27.819 ;
        RECT  15.9 2.137 16.02 27.819 ;
        RECT  13.2 2.137 13.32 27.819 ;
        RECT  10.5 2.137 10.62 27.819 ;
        RECT  7.8 2.137 7.92 27.819 ;
        RECT  5.1 2.137 5.22 27.819 ;
        RECT  2.4 2.137 2.52 27.819 ;
    END
  END VSS
  # OT_OBS_CLOSED layer=M5 d_um=1.536 added=12
  OBS
    LAYER RVTN ;
     RECT  2.16 2.16 62.586 2.295 ;
     RECT  2.16 2.565 62.586 2.835 ;
     RECT  2.16 3.105 62.586 3.375 ;
     RECT  2.16 3.645 62.586 3.915 ;
     RECT  2.16 4.185 62.586 4.455 ;
     RECT  2.16 4.725 62.586 4.995 ;
     RECT  2.16 5.265 62.586 5.535 ;
     RECT  2.16 5.805 62.586 6.075 ;
     RECT  2.16 6.345 62.586 6.615 ;
     RECT  2.16 6.885 62.586 7.155 ;
     RECT  2.16 7.425 62.586 7.695 ;
     RECT  2.16 7.965 62.586 8.235 ;
     RECT  2.16 8.505 62.586 8.775 ;
     RECT  2.16 9.045 62.586 9.315 ;
     RECT  2.16 9.585 62.586 9.855 ;
     RECT  2.16 10.125 62.586 10.395 ;
     RECT  2.16 10.665 62.586 10.935 ;
     RECT  2.16 11.205 62.586 11.475 ;
     RECT  2.16 11.745 62.586 12.015 ;
     RECT  2.16 12.285 62.586 12.555 ;
     RECT  2.16 12.825 62.586 13.095 ;
     RECT  2.16 13.365 62.586 13.635 ;
     RECT  2.16 13.905 62.586 14.175 ;
     RECT  2.16 14.445 62.586 14.715 ;
     RECT  2.16 14.985 62.586 15.255 ;
     RECT  2.16 15.525 62.586 15.795 ;
     RECT  2.16 16.065 62.586 16.335 ;
     RECT  2.16 16.605 62.586 16.875 ;
     RECT  2.16 17.145 62.586 17.415 ;
     RECT  2.16 17.685 62.586 17.955 ;
     RECT  2.16 18.225 62.586 18.495 ;
     RECT  2.16 18.765 62.586 19.035 ;
     RECT  2.16 19.305 62.586 19.575 ;
     RECT  2.16 19.845 62.586 20.115 ;
     RECT  2.16 20.385 62.586 20.655 ;
     RECT  2.16 20.925 62.586 21.195 ;
     RECT  2.16 21.465 62.586 21.735 ;
     RECT  2.16 22.005 62.586 22.275 ;
     RECT  2.16 22.545 62.586 22.815 ;
     RECT  2.16 23.085 62.586 23.355 ;
     RECT  2.16 23.625 62.586 23.895 ;
     RECT  2.16 24.165 62.586 24.435 ;
     RECT  2.16 24.705 62.586 24.975 ;
     RECT  2.16 25.245 62.586 25.515 ;
     RECT  2.16 25.785 62.586 26.055 ;
     RECT  2.16 26.325 62.586 26.595 ;
     RECT  2.16 26.865 62.586 27.135 ;
     RECT  2.16 27.405 62.586 27.675 ;
    LAYER RVTP ;
     RECT  2.16 2.295 62.586 2.565 ;
     RECT  2.16 2.835 62.586 3.105 ;
     RECT  2.16 3.375 62.586 3.645 ;
     RECT  2.16 3.915 62.586 4.185 ;
     RECT  2.16 4.455 62.586 4.725 ;
     RECT  2.16 4.995 62.586 5.265 ;
     RECT  2.16 5.535 62.586 5.805 ;
     RECT  2.16 6.075 62.586 6.345 ;
     RECT  2.16 6.615 62.586 6.885 ;
     RECT  2.16 7.155 62.586 7.425 ;
     RECT  2.16 7.695 62.586 7.965 ;
     RECT  2.16 8.235 62.586 8.505 ;
     RECT  2.16 8.775 62.586 9.045 ;
     RECT  2.16 9.315 62.586 9.585 ;
     RECT  2.16 9.855 62.586 10.125 ;
     RECT  2.16 10.395 62.586 10.665 ;
     RECT  2.16 10.935 62.586 11.205 ;
     RECT  2.16 11.475 62.586 11.745 ;
     RECT  2.16 12.015 62.586 12.285 ;
     RECT  2.16 12.555 62.586 12.825 ;
     RECT  2.16 13.095 62.586 13.365 ;
     RECT  2.16 13.635 62.586 13.905 ;
     RECT  2.16 14.175 62.586 14.445 ;
     RECT  2.16 14.715 62.586 14.985 ;
     RECT  2.16 15.255 62.586 15.525 ;
     RECT  2.16 15.795 62.586 16.065 ;
     RECT  2.16 16.335 62.586 16.605 ;
     RECT  2.16 16.875 62.586 17.145 ;
     RECT  2.16 17.415 62.586 17.685 ;
     RECT  2.16 17.955 62.586 18.225 ;
     RECT  2.16 18.495 62.586 18.765 ;
     RECT  2.16 19.035 62.586 19.305 ;
     RECT  2.16 19.575 62.586 19.845 ;
     RECT  2.16 20.115 62.586 20.385 ;
     RECT  2.16 20.655 62.586 20.925 ;
     RECT  2.16 21.195 62.586 21.465 ;
     RECT  2.16 21.735 62.586 22.005 ;
     RECT  2.16 22.275 62.586 22.545 ;
     RECT  2.16 22.815 62.586 23.085 ;
     RECT  2.16 23.355 62.586 23.625 ;
     RECT  2.16 23.895 62.586 24.165 ;
     RECT  2.16 24.435 62.586 24.705 ;
     RECT  2.16 24.975 62.586 25.245 ;
     RECT  2.16 25.515 62.586 25.785 ;
     RECT  2.16 26.055 62.586 26.325 ;
     RECT  2.16 26.595 62.586 26.865 ;
     RECT  2.16 27.135 62.586 27.405 ;
     RECT  2.16 27.675 62.586 27.81 ;
    LAYER M1 ;
     RECT  2.16 2.151 62.586 27.819 ;
    LAYER M2 ;
     RECT  26.455 28.764 26.671 28.782 ;
     RECT  2.16 2.151 26.779 27.819 ;
     RECT  26.671 28.764 27.643 28.818 ;
     RECT  26.275 30.186 27.643 30.204 ;
     RECT  26.779 2.151 27.679 27.864 ;
     RECT  27.679 2.151 27.967 27.9 ;
     RECT  27.643 28.764 27.967 30.204 ;
     RECT  27.967 2.151 28.535 30.204 ;
     RECT  28.535 2.151 28.895 30.168 ;
     RECT  28.895 2.151 29.147 30.096 ;
     RECT  29.147 2.151 29.219 28.818 ;
     RECT  29.147 29.961 29.695 30.096 ;
     RECT  29.219 2.151 30.155 28.476 ;
     RECT  30.155 2.151 30.299 27.9 ;
     RECT  29.695 29.961 30.839 30.168 ;
     RECT  30.299 2.151 32.215 27.864 ;
     RECT  30.839 30.006 32.539 30.168 ;
     RECT  32.539 29.961 32.819 30.168 ;
     RECT  32.819 30.006 33.071 30.168 ;
     RECT  33.071 30.006 33.143 30.024 ;
     RECT  32.215 2.151 34.547 28.008 ;
     RECT  32.431 28.764 36.131 28.782 ;
     RECT  34.547 2.151 37.139 27.936 ;
     RECT  37.139 2.151 60.251 27.864 ;
     RECT  60.251 2.151 62.586 27.819 ;
     RECT  62.586 6.786 62.699 19.494 ;
     RECT  62.699 19.116 63.275 19.494 ;
     RECT  62.699 6.786 63.311 18.216 ;
     RECT  63.275 19.278 63.311 19.494 ;
     RECT  63.311 19.476 63.347 19.494 ;
     RECT  63.311 6.786 63.887 6.804 ;
     RECT  63.311 7.704 63.887 16.974 ;
     RECT  63.311 17.856 63.887 18.216 ;
     RECT  63.887 9.216 63.923 9.954 ;
     RECT  63.887 11.916 63.923 13.464 ;
     RECT  63.887 14.652 63.923 14.67 ;
     RECT  63.887 16.11 63.923 16.974 ;
     RECT  63.887 7.74 63.959 8.334 ;
     RECT  63.923 12.798 63.959 12.816 ;
     RECT  63.923 16.956 63.959 16.974 ;
     RECT  63.923 9.36 63.995 9.378 ;
     RECT  63.923 16.146 63.995 16.164 ;
     RECT  64.651 9.486 64.751 9.504 ;
     RECT  64.651 11.826 64.751 12.78 ;
     RECT  64.651 14.112 64.751 14.13 ;
     RECT  64.651 17.811 64.751 18.144 ;
    LAYER M3 ;
     RECT  2.415 2.143 2.505 2.413 ;
     RECT  5.115 2.143 5.205 2.413 ;
     RECT  7.815 2.143 7.905 2.413 ;
     RECT  10.515 2.143 10.605 2.413 ;
     RECT  13.215 2.143 13.305 2.413 ;
     RECT  15.915 2.143 16.005 2.413 ;
     RECT  18.615 2.143 18.705 2.413 ;
     RECT  21.315 2.143 21.405 2.413 ;
     RECT  24.015 2.143 24.105 2.413 ;
     RECT  26.715 2.143 26.805 2.413 ;
     RECT  29.415 2.143 29.505 2.413 ;
     RECT  32.115 2.143 32.205 2.413 ;
     RECT  34.815 2.143 34.905 2.413 ;
     RECT  37.515 2.143 37.605 2.413 ;
     RECT  40.215 2.143 40.305 2.413 ;
     RECT  42.915 2.143 43.005 2.413 ;
     RECT  45.615 2.143 45.705 2.413 ;
     RECT  48.315 2.143 48.405 2.413 ;
     RECT  51.015 2.143 51.105 2.413 ;
     RECT  53.715 2.143 53.805 2.413 ;
     RECT  56.415 2.143 56.505 2.413 ;
     RECT  59.115 2.143 59.205 2.413 ;
     RECT  61.815 2.143 61.905 2.413 ;
     RECT  59.115 2.413 59.397 6.817 ;
     RECT  62.964 6.955 62.982 7.045 ;
     RECT  63.864 6.781 63.882 7.045 ;
     RECT  61.815 2.413 62.097 7.147 ;
     RECT  62.964 7.045 63.882 7.147 ;
     RECT  61.815 7.147 63.882 7.339 ;
     RECT  31.068 7.087 31.086 7.357 ;
     RECT  31.068 7.357 31.266 7.501 ;
     RECT  32.115 2.413 32.397 7.501 ;
     RECT  34.815 2.413 35.097 7.501 ;
     RECT  31.068 7.501 32.397 7.627 ;
     RECT  29.415 2.413 29.697 7.699 ;
     RECT  30.636 7.627 32.397 7.699 ;
     RECT  34.74 7.501 35.097 7.699 ;
     RECT  61.815 7.339 63.954 7.735 ;
     RECT  29.415 7.699 32.397 7.861 ;
     RECT  29.016 7.861 32.397 7.889 ;
     RECT  34.668 7.699 35.097 7.889 ;
     RECT  30.636 7.889 32.397 7.915 ;
     RECT  61.56 7.735 63.954 8.069 ;
     RECT  42.915 2.413 43.197 8.131 ;
     RECT  44.784 8.131 44.802 8.231 ;
     RECT  61.815 8.069 63.954 8.525 ;
     RECT  30.636 7.915 32.85 8.581 ;
     RECT  30.636 8.581 33.498 8.707 ;
     RECT  30.636 8.707 33.57 8.771 ;
     RECT  30.636 8.771 32.778 8.851 ;
     RECT  34.815 7.889 35.097 8.851 ;
     RECT  33.552 8.771 33.57 8.971 ;
     RECT  30.6 8.851 32.778 9.005 ;
     RECT  30.6 9.005 32.49 9.085 ;
     RECT  30.528 9.085 32.49 9.319 ;
     RECT  33.552 8.971 33.93 9.319 ;
     RECT  34.776 8.851 35.097 9.319 ;
     RECT  61.815 8.525 63.918 9.355 ;
     RECT  61.815 9.355 63.99 9.451 ;
     RECT  61.815 9.451 64.674 9.481 ;
     RECT  33.552 9.319 35.097 9.499 ;
     RECT  61.815 9.481 64.746 9.509 ;
     RECT  64.728 9.509 64.746 9.533 ;
     RECT  61.815 9.509 63.99 9.581 ;
     RECT  38.664 9.547 38.79 9.677 ;
     RECT  46.764 9.547 46.782 9.677 ;
     RECT  54.72 9.547 54.738 9.677 ;
     RECT  30.456 9.319 32.49 9.787 ;
     RECT  30.456 9.787 32.562 9.859 ;
     RECT  33.408 9.499 35.097 9.859 ;
     RECT  61.815 9.581 63.918 9.965 ;
     RECT  61.815 9.965 63.882 10.435 ;
     RECT  29.016 7.889 29.697 10.471 ;
     RECT  30.456 9.859 35.097 10.471 ;
     RECT  29.016 10.471 35.097 10.499 ;
     RECT  58.392 6.817 59.397 10.705 ;
     RECT  29.016 10.499 33.066 11.227 ;
     RECT  33.804 10.499 35.097 11.227 ;
     RECT  38.772 11.179 38.79 11.227 ;
     RECT  46.764 11.179 46.782 11.227 ;
     RECT  54.72 11.179 54.738 11.227 ;
     RECT  38.772 11.227 38.862 11.405 ;
     RECT  46.764 11.227 46.854 11.405 ;
     RECT  54.72 11.227 54.81 11.405 ;
     RECT  60.444 9.085 60.462 11.551 ;
     RECT  61.488 10.435 63.882 11.563 ;
     RECT  37.515 2.413 37.797 11.755 ;
     RECT  29.016 11.227 35.097 11.785 ;
     RECT  29.016 11.785 35.154 11.821 ;
     RECT  60.444 11.551 60.75 11.821 ;
     RECT  61.488 11.563 63.918 11.821 ;
     RECT  64.728 11.803 64.746 11.821 ;
     RECT  38.772 11.405 38.79 11.837 ;
     RECT  46.764 11.405 46.782 11.837 ;
     RECT  54.72 11.405 54.738 11.837 ;
     RECT  60.444 11.821 63.918 11.939 ;
     RECT  37.515 11.755 37.818 11.981 ;
     RECT  29.016 11.821 35.226 12.289 ;
     RECT  29.016 12.289 35.298 12.325 ;
     RECT  38.664 12.181 38.754 12.389 ;
     RECT  60.444 11.939 60.642 12.389 ;
     RECT  29.016 12.325 35.622 12.479 ;
     RECT  61.488 11.939 63.918 12.514 ;
     RECT  64.656 11.821 64.746 12.514 ;
     RECT  37.515 11.981 37.797 12.631 ;
     RECT  38.736 12.389 38.754 12.721 ;
     RECT  36.828 12.631 37.797 12.749 ;
     RECT  61.488 12.514 64.746 12.785 ;
     RECT  64.728 12.785 64.746 12.797 ;
     RECT  36.648 12.757 36.774 12.811 ;
     RECT  61.488 12.785 63.954 12.821 ;
     RECT  38.736 12.721 38.79 12.829 ;
     RECT  38.736 12.829 38.862 12.929 ;
     RECT  61.488 12.821 63.918 13.019 ;
     RECT  60.444 12.389 60.462 13.291 ;
     RECT  61.488 13.019 62.406 13.291 ;
     RECT  36.396 12.811 36.774 13.333 ;
     RECT  29.016 12.479 35.334 13.441 ;
     RECT  36.252 13.333 36.774 13.441 ;
     RECT  37.515 12.749 37.797 13.441 ;
     RECT  38.736 12.929 38.826 13.441 ;
     RECT  63.288 13.019 63.918 13.469 ;
     RECT  29.016 13.441 36.774 13.531 ;
     RECT  37.515 13.441 38.826 13.531 ;
     RECT  29.016 13.531 38.826 13.559 ;
     RECT  58.392 10.705 59.562 13.579 ;
     RECT  38.736 13.559 38.826 13.666 ;
     RECT  38.736 13.666 38.862 13.675 ;
     RECT  58.104 13.579 59.562 13.703 ;
     RECT  60.444 13.291 62.406 13.739 ;
     RECT  61.488 13.739 62.406 13.771 ;
     RECT  63.288 13.469 63.882 13.771 ;
     RECT  58.392 13.703 59.562 13.837 ;
     RECT  60.444 13.739 60.462 13.837 ;
     RECT  58.392 13.837 60.462 13.901 ;
     RECT  2.415 2.413 2.697 14.071 ;
     RECT  56.415 2.413 56.697 14.107 ;
     RECT  64.656 14.059 64.674 14.107 ;
     RECT  64.656 14.107 64.746 14.135 ;
     RECT  64.728 14.135 64.746 14.144 ;
     RECT  38.736 13.675 38.898 14.207 ;
     RECT  2.415 14.071 2.718 14.215 ;
     RECT  61.488 13.771 63.882 14.279 ;
     RECT  56.415 14.107 57.006 14.405 ;
     RECT  63.288 14.279 63.882 14.443 ;
     RECT  29.016 13.559 37.797 14.449 ;
     RECT  2.415 14.215 2.862 14.521 ;
     RECT  63.288 14.443 63.918 14.675 ;
     RECT  2.415 14.521 3.438 14.731 ;
     RECT  2.304 14.731 3.438 14.881 ;
     RECT  60.444 13.901 60.462 14.923 ;
     RECT  61.488 14.279 62.406 14.923 ;
     RECT  29.016 14.449 38.25 14.953 ;
     RECT  2.304 14.881 4.014 15.061 ;
     RECT  29.016 14.953 38.682 15.061 ;
     RECT  39.42 14.611 39.474 15.061 ;
     RECT  2.304 15.061 4.266 15.287 ;
     RECT  60.444 14.923 62.406 15.323 ;
     RECT  61.488 15.323 62.406 15.376 ;
     RECT  63.288 14.675 63.882 15.376 ;
     RECT  2.412 15.287 4.266 15.389 ;
     RECT  42.915 8.131 43.902 15.493 ;
     RECT  42.66 15.493 43.902 15.629 ;
     RECT  18.615 2.413 18.897 15.691 ;
     RECT  28.296 15.061 39.474 15.719 ;
     RECT  46.764 15.691 46.782 15.821 ;
     RECT  54.72 15.691 54.738 15.821 ;
     RECT  2.412 15.389 3.834 15.989 ;
     RECT  40.215 2.413 40.497 15.997 ;
     RECT  2.412 15.989 3.726 16.013 ;
     RECT  3.42 16.013 3.726 16.025 ;
     RECT  40.215 15.997 40.518 16.097 ;
     RECT  61.488 15.376 63.882 16.105 ;
     RECT  2.412 16.013 2.697 16.109 ;
     RECT  3.42 16.025 3.438 16.109 ;
     RECT  61.488 16.105 63.918 16.141 ;
     RECT  61.488 16.141 63.99 16.301 ;
     RECT  56.415 14.405 56.697 16.303 ;
     RECT  56.415 16.303 57.042 16.589 ;
     RECT  28.296 15.719 39.33 16.609 ;
     RECT  40.215 16.097 40.497 16.609 ;
     RECT  42.732 15.629 43.902 16.799 ;
     RECT  28.296 16.609 40.497 16.871 ;
     RECT  28.296 16.871 39.186 17.069 ;
     RECT  61.488 16.301 63.954 17.165 ;
     RECT  60.444 15.323 60.75 17.179 ;
     RECT  58.392 13.901 59.562 17.347 ;
     RECT  60.408 17.179 60.75 17.347 ;
     RECT  58.392 17.347 60.75 17.453 ;
     RECT  61.488 17.165 63.882 17.519 ;
     RECT  64.728 17.755 64.746 17.8 ;
     RECT  64.656 17.8 64.746 18.149 ;
     RECT  64.728 18.149 64.746 18.173 ;
     RECT  63.864 17.519 63.882 18.227 ;
     RECT  61.488 17.519 62.622 18.283 ;
     RECT  61.488 18.283 62.766 18.379 ;
     RECT  61.488 18.379 62.838 18.763 ;
     RECT  61.488 18.763 63.27 18.955 ;
     RECT  61.488 18.955 63.306 19.103 ;
     RECT  63.252 19.103 63.306 19.139 ;
     RECT  63.288 19.139 63.306 19.147 ;
     RECT  63.288 19.147 63.342 19.301 ;
     RECT  60.444 17.453 60.75 19.345 ;
     RECT  61.488 19.103 62.097 19.345 ;
     RECT  63.324 19.301 63.342 19.499 ;
     RECT  58.392 17.453 59.562 19.615 ;
     RECT  60.444 19.345 62.097 19.615 ;
     RECT  58.392 19.615 62.097 19.643 ;
     RECT  58.392 19.643 60.75 19.661 ;
     RECT  17.928 15.691 18.897 20.281 ;
     RECT  17.928 20.281 19.35 20.333 ;
     RECT  17.928 20.333 19.134 20.579 ;
     RECT  15.084 15.187 15.102 20.615 ;
     RECT  17.928 20.579 18.954 20.723 ;
     RECT  18.615 20.723 18.954 20.909 ;
     RECT  26.715 2.413 26.997 21.211 ;
     RECT  26.715 21.211 27.054 21.541 ;
     RECT  45.615 2.413 45.897 22.621 ;
     RECT  47.016 22.207 47.034 22.621 ;
     RECT  26.715 21.541 27.342 22.739 ;
     RECT  26.715 22.739 27.234 22.891 ;
     RECT  28.296 17.069 39.042 23.275 ;
     RECT  26.208 22.891 27.234 23.309 ;
     RECT  26.208 23.309 26.997 23.371 ;
     RECT  41.796 13.027 41.814 23.629 ;
     RECT  45.615 22.621 47.034 23.791 ;
     RECT  26.1 23.371 26.997 23.819 ;
     RECT  25.092 23.791 25.11 23.885 ;
     RECT  45.615 23.791 47.538 23.899 ;
     RECT  48.315 2.413 48.597 23.899 ;
     RECT  45.615 23.899 48.597 24.089 ;
     RECT  45.615 24.089 47.466 24.125 ;
     RECT  41.544 23.629 41.814 24.139 ;
     RECT  47.016 24.125 47.466 24.173 ;
     RECT  41.544 24.139 42.102 24.233 ;
     RECT  47.016 24.173 47.034 24.233 ;
     RECT  28.044 23.275 39.042 24.427 ;
     RECT  27.72 24.427 39.042 24.467 ;
     RECT  41.544 24.233 41.958 24.475 ;
     RECT  41.292 24.475 41.958 24.511 ;
     RECT  26.715 23.819 26.997 24.571 ;
     RECT  41.22 24.511 41.958 24.773 ;
     RECT  60.444 19.661 60.75 24.809 ;
     RECT  41.544 24.773 41.958 24.899 ;
     RECT  42.915 16.799 43.902 24.971 ;
     RECT  26.715 24.571 27.09 25.387 ;
     RECT  28.116 24.467 39.042 25.439 ;
     RECT  58.392 19.661 59.562 25.439 ;
     RECT  26.715 25.387 27.342 25.591 ;
     RECT  28.116 25.439 38.646 25.591 ;
     RECT  41.544 24.899 41.814 25.709 ;
     RECT  51.015 2.413 51.297 26.329 ;
     RECT  60.444 24.809 60.462 26.365 ;
     RECT  61.488 19.643 62.097 26.365 ;
     RECT  26.715 25.591 38.646 26.401 ;
     RECT  48.315 24.089 48.597 26.401 ;
     RECT  46.764 26.329 46.782 26.429 ;
     RECT  51.015 26.329 51.354 26.429 ;
     RECT  54.72 26.401 54.738 26.519 ;
     RECT  58.392 25.439 59.397 26.519 ;
     RECT  60.444 26.365 62.097 26.519 ;
     RECT  48.276 26.401 48.597 26.621 ;
     RECT  26.676 26.401 38.646 26.941 ;
     RECT  61.488 26.519 62.097 27.059 ;
     RECT  26.46 26.941 38.646 27.067 ;
     RECT  58.788 26.519 59.397 27.095 ;
     RECT  26.46 27.067 39.366 27.103 ;
     RECT  26.46 27.103 39.402 27.239 ;
     RECT  26.46 27.239 39.366 27.329 ;
     RECT  39.348 27.329 39.366 27.509 ;
     RECT  2.415 16.109 2.697 27.557 ;
     RECT  5.115 2.413 5.397 27.557 ;
     RECT  7.815 2.413 8.097 27.557 ;
     RECT  10.515 2.413 10.797 27.557 ;
     RECT  13.215 2.413 13.497 27.557 ;
     RECT  15.915 2.413 16.197 27.557 ;
     RECT  18.615 20.909 18.897 27.557 ;
     RECT  21.315 2.413 21.597 27.557 ;
     RECT  24.015 2.413 24.297 27.557 ;
     RECT  40.215 16.871 40.497 27.557 ;
     RECT  42.915 24.971 43.197 27.557 ;
     RECT  45.615 24.125 45.897 27.557 ;
     RECT  48.315 26.621 48.597 27.557 ;
     RECT  51.015 26.429 51.297 27.557 ;
     RECT  53.715 2.413 53.997 27.557 ;
     RECT  56.415 16.589 56.697 27.557 ;
     RECT  59.115 27.095 59.397 27.557 ;
     RECT  61.815 27.059 62.097 27.557 ;
     RECT  26.46 27.329 38.07 27.599 ;
     RECT  60.444 26.519 60.462 27.599 ;
     RECT  26.46 27.599 37.854 27.671 ;
     RECT  26.46 27.671 33.75 27.715 ;
     RECT  2.607 27.557 2.697 27.827 ;
     RECT  5.307 27.557 5.397 27.827 ;
     RECT  8.007 27.557 8.097 27.827 ;
     RECT  10.707 27.557 10.797 27.827 ;
     RECT  13.407 27.557 13.497 27.827 ;
     RECT  16.107 27.557 16.197 27.827 ;
     RECT  18.807 27.557 18.897 27.827 ;
     RECT  21.507 27.557 21.597 27.827 ;
     RECT  24.207 27.557 24.297 27.827 ;
     RECT  34.524 27.671 37.854 27.827 ;
     RECT  40.407 27.557 40.497 27.827 ;
     RECT  43.107 27.557 43.197 27.827 ;
     RECT  45.807 27.557 45.897 27.827 ;
     RECT  48.507 27.557 48.597 27.827 ;
     RECT  51.207 27.557 51.297 27.827 ;
     RECT  53.907 27.557 53.997 27.827 ;
     RECT  56.607 27.557 56.697 27.827 ;
     RECT  59.307 27.557 59.397 27.827 ;
     RECT  62.007 27.557 62.097 27.827 ;
     RECT  60.228 27.751 60.246 27.869 ;
     RECT  26.28 27.715 33.75 27.905 ;
     RECT  34.524 27.827 34.938 28.013 ;
     RECT  35.676 27.827 37.854 28.349 ;
     RECT  35.676 28.349 36.126 28.445 ;
     RECT  36.936 28.349 37.854 28.493 ;
     RECT  26.28 27.905 33.102 28.781 ;
     RECT  37.548 28.493 37.854 28.781 ;
     RECT  36.108 28.445 36.126 28.787 ;
     RECT  26.28 28.781 26.694 28.823 ;
     RECT  37.548 28.781 37.566 29.357 ;
     RECT  27.648 28.781 33.102 29.561 ;
     RECT  27.792 29.561 33.102 29.633 ;
     RECT  27.936 29.633 33.102 29.741 ;
     RECT  28.08 29.741 33.102 30.001 ;
     RECT  28.08 30.001 33.138 30.125 ;
     RECT  34.668 28.013 34.686 30.125 ;
     RECT  28.512 30.125 33.138 30.179 ;
     RECT  28.512 30.179 28.548 30.18 ;
     RECT  28.566 30.179 28.62 30.18 ;
     RECT  28.638 30.179 28.692 30.18 ;
     RECT  28.71 30.179 28.764 30.18 ;
     RECT  28.782 30.179 28.836 30.18 ;
     RECT  28.854 30.179 28.908 30.18 ;
     RECT  28.926 30.179 28.98 30.18 ;
     RECT  28.998 30.179 29.052 30.18 ;
     RECT  29.07 30.179 29.124 30.18 ;
     RECT  29.142 30.179 29.196 30.18 ;
     RECT  29.214 30.179 29.268 30.18 ;
     RECT  29.286 30.179 29.34 30.18 ;
     RECT  29.358 30.179 29.412 30.18 ;
     RECT  29.43 30.179 29.484 30.18 ;
     RECT  29.502 30.179 29.556 30.18 ;
     RECT  29.574 30.179 29.628 30.18 ;
     RECT  29.646 30.179 29.7 30.18 ;
     RECT  29.718 30.179 29.772 30.18 ;
     RECT  29.79 30.179 29.844 30.18 ;
     RECT  29.862 30.179 29.916 30.18 ;
     RECT  29.934 30.179 29.988 30.18 ;
     RECT  30.006 30.179 30.06 30.18 ;
     RECT  30.078 30.179 30.132 30.18 ;
     RECT  30.15 30.179 30.204 30.18 ;
     RECT  30.222 30.179 30.276 30.18 ;
     RECT  30.294 30.179 30.348 30.18 ;
     RECT  30.366 30.179 30.42 30.18 ;
     RECT  30.438 30.179 30.492 30.18 ;
     RECT  30.51 30.179 30.564 30.18 ;
     RECT  30.582 30.179 30.636 30.18 ;
     RECT  30.654 30.179 30.708 30.18 ;
     RECT  30.726 30.179 30.78 30.18 ;
     RECT  30.798 30.179 30.852 30.18 ;
     RECT  30.87 30.179 30.924 30.18 ;
     RECT  30.942 30.179 30.996 30.18 ;
     RECT  31.014 30.179 31.068 30.18 ;
     RECT  31.086 30.179 31.14 30.18 ;
     RECT  31.158 30.179 31.212 30.18 ;
     RECT  31.23 30.179 31.284 30.18 ;
     RECT  31.302 30.179 31.356 30.18 ;
     RECT  31.374 30.179 31.428 30.18 ;
     RECT  31.446 30.179 31.5 30.18 ;
     RECT  31.518 30.179 31.572 30.18 ;
     RECT  31.59 30.179 31.644 30.18 ;
     RECT  31.662 30.179 31.716 30.18 ;
     RECT  31.734 30.179 31.788 30.18 ;
     RECT  31.806 30.179 31.86 30.18 ;
     RECT  31.878 30.179 31.932 30.18 ;
     RECT  31.95 30.179 32.004 30.18 ;
     RECT  32.022 30.179 32.076 30.18 ;
     RECT  32.094 30.179 32.148 30.18 ;
     RECT  32.166 30.179 32.22 30.18 ;
     RECT  32.238 30.179 32.292 30.18 ;
     RECT  32.31 30.179 32.364 30.18 ;
     RECT  32.382 30.179 32.436 30.18 ;
     RECT  32.454 30.179 32.508 30.18 ;
     RECT  32.526 30.179 32.58 30.18 ;
     RECT  32.598 30.179 32.652 30.18 ;
     RECT  32.67 30.179 32.724 30.18 ;
     RECT  32.742 30.179 32.796 30.18 ;
     RECT  32.814 30.179 32.868 30.18 ;
     RECT  32.886 30.179 32.94 30.18 ;
     RECT  32.958 30.179 33.012 30.18 ;
     RECT  33.03 30.179 33.084 30.18 ;
     RECT  33.102 30.179 33.138 30.18 ;
     RECT  28.512 30.18 28.548 30.204 ;
     RECT  28.566 30.18 28.62 30.204 ;
     RECT  28.638 30.18 28.692 30.204 ;
     RECT  28.71 30.18 28.764 30.204 ;
     RECT  28.782 30.18 28.836 30.204 ;
     RECT  28.854 30.18 28.908 30.204 ;
     RECT  28.926 30.18 28.98 30.204 ;
     RECT  28.998 30.18 29.052 30.204 ;
     RECT  29.07 30.18 29.124 30.204 ;
     RECT  29.142 30.18 29.196 30.204 ;
     RECT  29.214 30.18 29.268 30.204 ;
     RECT  29.286 30.18 29.34 30.204 ;
     RECT  29.358 30.18 29.412 30.204 ;
     RECT  29.43 30.18 29.484 30.204 ;
     RECT  29.502 30.18 29.556 30.204 ;
     RECT  29.574 30.18 29.628 30.204 ;
     RECT  29.646 30.18 29.7 30.204 ;
     RECT  29.718 30.18 29.772 30.204 ;
     RECT  29.79 30.18 29.844 30.204 ;
     RECT  29.862 30.18 29.916 30.204 ;
     RECT  29.934 30.18 29.988 30.204 ;
     RECT  30.006 30.18 30.06 30.204 ;
     RECT  30.078 30.18 30.132 30.204 ;
     RECT  30.15 30.18 30.204 30.204 ;
     RECT  30.222 30.18 30.276 30.204 ;
     RECT  30.294 30.18 30.348 30.204 ;
     RECT  30.366 30.18 30.42 30.204 ;
     RECT  30.438 30.18 30.492 30.204 ;
     RECT  30.51 30.18 30.564 30.204 ;
     RECT  30.582 30.18 30.636 30.204 ;
     RECT  30.654 30.18 30.708 30.204 ;
     RECT  30.726 30.18 30.78 30.204 ;
     RECT  30.798 30.18 30.852 30.204 ;
     RECT  30.87 30.18 30.924 30.204 ;
     RECT  30.942 30.18 30.996 30.204 ;
     RECT  31.014 30.18 31.068 30.204 ;
     RECT  31.086 30.18 31.14 30.204 ;
     RECT  31.158 30.18 31.212 30.204 ;
     RECT  31.23 30.18 31.284 30.204 ;
     RECT  31.302 30.18 31.356 30.204 ;
     RECT  31.374 30.18 31.428 30.204 ;
     RECT  31.446 30.18 31.5 30.204 ;
     RECT  31.518 30.18 31.572 30.204 ;
     RECT  31.59 30.18 31.644 30.204 ;
     RECT  31.662 30.18 31.716 30.204 ;
     RECT  31.734 30.18 31.788 30.204 ;
     RECT  31.806 30.18 31.86 30.204 ;
     RECT  31.878 30.18 31.932 30.204 ;
     RECT  31.95 30.18 32.004 30.204 ;
     RECT  32.022 30.18 32.076 30.204 ;
     RECT  32.094 30.18 32.148 30.204 ;
     RECT  32.166 30.18 32.22 30.204 ;
     RECT  32.238 30.18 32.292 30.204 ;
     RECT  32.31 30.18 32.364 30.204 ;
     RECT  32.382 30.18 32.436 30.204 ;
     RECT  32.454 30.18 32.508 30.204 ;
     RECT  32.526 30.18 32.58 30.204 ;
     RECT  32.598 30.18 32.652 30.204 ;
     RECT  32.67 30.18 32.724 30.204 ;
     RECT  32.742 30.18 32.796 30.204 ;
     RECT  32.814 30.18 32.868 30.204 ;
     RECT  32.886 30.18 32.94 30.204 ;
     RECT  32.958 30.18 33.012 30.204 ;
     RECT  33.03 30.18 33.084 30.204 ;
     RECT  26.28 28.823 26.298 30.209 ;
     RECT  28.512 30.204 28.53 30.209 ;
    LAYER M4 ;
     RECT  0.084 14.832 2.293 14.856 ;
     RECT  0.06 14.856 2.293 14.928 ;
     RECT  0.084 14.928 2.293 14.952 ;
     RECT  0.06 14.952 2.293 15.024 ;
     RECT  0.084 15.024 2.293 15.048 ;
     RECT  2.293 14.112 2.401 15.768 ;
     RECT  2.401 14.112 2.408 16.104 ;
     RECT  2.408 2.148 2.512 27.552 ;
     RECT  2.512 2.418 2.6 27.552 ;
     RECT  2.6 2.418 2.704 27.822 ;
     RECT  2.704 14.112 2.729 16.104 ;
     RECT  2.729 14.736 2.867 16.104 ;
     RECT  2.867 14.784 3.449 16.104 ;
     RECT  3.449 14.928 3.953 15.384 ;
     RECT  2.704 22.8 4.261 22.824 ;
     RECT  3.953 15.36 5.108 15.384 ;
     RECT  4.261 21.936 5.108 22.824 ;
     RECT  5.108 2.148 5.212 27.552 ;
     RECT  5.212 2.418 5.3 27.552 ;
     RECT  5.3 2.418 5.404 27.822 ;
     RECT  5.404 21.936 7.808 22.824 ;
     RECT  7.808 2.148 7.912 27.552 ;
     RECT  7.912 2.418 8 27.552 ;
     RECT  8 2.418 8.104 27.822 ;
     RECT  8.104 21.936 10.508 22.824 ;
     RECT  10.508 2.148 10.612 27.552 ;
     RECT  10.612 2.418 10.7 27.552 ;
     RECT  10.7 2.418 10.804 27.822 ;
     RECT  10.804 21.936 13.208 22.824 ;
     RECT  13.208 2.148 13.312 27.552 ;
     RECT  13.312 2.418 13.4 27.552 ;
     RECT  13.4 2.418 13.504 27.822 ;
     RECT  13.504 21.936 15.908 22.824 ;
     RECT  15.908 2.148 16.012 27.552 ;
     RECT  16.012 2.418 16.1 27.552 ;
     RECT  16.1 2.418 16.204 27.822 ;
     RECT  18.205 20.4 18.277 20.424 ;
     RECT  18.277 20.4 18.608 20.616 ;
     RECT  16.204 21.936 18.608 22.824 ;
     RECT  18.608 2.148 18.712 27.552 ;
     RECT  18.712 2.418 18.8 27.552 ;
     RECT  18.8 2.418 18.904 27.822 ;
     RECT  18.904 20.304 21.308 20.904 ;
     RECT  18.904 21.936 21.308 22.824 ;
     RECT  21.308 2.148 21.412 27.552 ;
     RECT  21.412 2.418 21.5 27.552 ;
     RECT  21.5 2.418 21.604 27.822 ;
     RECT  21.604 20.304 24.008 20.904 ;
     RECT  21.604 21.936 24.008 22.824 ;
     RECT  24.008 2.148 24.112 27.552 ;
     RECT  24.112 2.418 24.2 27.552 ;
     RECT  24.2 2.418 24.304 27.822 ;
     RECT  24.304 21.936 26.089 22.824 ;
     RECT  24.304 23.856 26.089 23.88 ;
     RECT  26.089 21.936 26.101 23.88 ;
     RECT  24.304 20.304 26.708 20.904 ;
     RECT  26.101 21.936 26.708 24.744 ;
     RECT  26.665 26.544 26.708 26.568 ;
     RECT  26.708 2.148 26.812 27.552 ;
     RECT  26.812 2.418 26.9 27.552 ;
     RECT  26.9 2.418 27.004 27.822 ;
     RECT  27.004 20.304 27.155 27.672 ;
     RECT  27.349 28.752 27.925 28.776 ;
     RECT  27.925 28.752 28.069 29.736 ;
     RECT  28.069 28.752 28.721 30.12 ;
     RECT  27.155 21.936 29.408 27.672 ;
     RECT  29.408 2.148 29.512 27.672 ;
     RECT  29.512 2.418 29.6 27.672 ;
     RECT  28.721 28.752 29.6 29.832 ;
     RECT  29.6 2.418 29.651 29.832 ;
     RECT  29.651 2.418 29.704 29.784 ;
     RECT  29.704 21.936 30.757 29.784 ;
     RECT  30.757 21.936 30.853 29.928 ;
     RECT  30.853 21.936 30.949 30.024 ;
     RECT  30.949 21.936 31.283 30.12 ;
     RECT  31.283 30.048 31.321 30.12 ;
     RECT  31.813 10.128 31.885 10.152 ;
     RECT  31.885 10.128 31.909 10.728 ;
     RECT  31.993 18.672 32.065 18.696 ;
     RECT  31.283 21.936 32.099 29.064 ;
     RECT  31.957 8.976 32.108 9 ;
     RECT  31.909 10.08 32.108 10.728 ;
     RECT  32.065 18.672 32.108 18.792 ;
     RECT  31.717 20.736 32.108 20.76 ;
     RECT  32.099 21.936 32.108 28.776 ;
     RECT  32.108 2.148 32.212 28.776 ;
     RECT  32.212 2.418 32.404 28.776 ;
     RECT  31.321 30.048 32.569 30.072 ;
     RECT  32.404 25.008 32.789 28.776 ;
     RECT  32.789 28.752 33.061 28.776 ;
     RECT  32.569 30.048 33.061 30.168 ;
     RECT  33.061 28.752 33.149 30.168 ;
     RECT  32.404 7.92 33.433 9 ;
     RECT  32.404 10.08 33.433 11.208 ;
     RECT  32.404 12.288 33.617 12.312 ;
     RECT  33.433 7.92 33.649 11.208 ;
     RECT  32.404 21.648 33.937 23.928 ;
     RECT  32.789 25.008 33.937 27.72 ;
     RECT  33.149 28.752 34.309 29.352 ;
     RECT  33.541 17.616 34.549 17.64 ;
     RECT  33.937 21.648 34.597 27.72 ;
     RECT  34.309 28.752 34.597 30.12 ;
     RECT  34.597 21.648 34.697 30.12 ;
     RECT  33.649 7.92 34.808 11.976 ;
     RECT  34.549 17.376 34.808 17.64 ;
     RECT  34.697 21.648 34.808 30.024 ;
     RECT  34.808 2.148 34.912 30.024 ;
     RECT  34.912 2.418 35.104 30.024 ;
     RECT  35.104 17.376 35.129 19.032 ;
     RECT  35.104 22.848 35.219 30.024 ;
     RECT  35.219 22.848 35.237 22.872 ;
     RECT  35.219 23.856 35.363 30.024 ;
     RECT  35.363 23.856 36.028 29.352 ;
     RECT  35.104 7.92 36.169 12.792 ;
     RECT  36.169 7.92 37.508 13.56 ;
     RECT  35.129 17.616 37.508 19.032 ;
     RECT  36.028 23.952 37.508 29.352 ;
     RECT  37.508 2.148 37.577 29.352 ;
     RECT  37.577 2.148 37.612 28.776 ;
     RECT  37.612 2.418 37.804 28.776 ;
     RECT  37.804 28.752 37.865 28.776 ;
     RECT  37.804 23.952 38.009 27.096 ;
     RECT  38.009 23.952 38.195 26.616 ;
     RECT  37.804 7.92 38.873 13.704 ;
     RECT  37.804 16.272 39.049 16.296 ;
     RECT  39.049 15.792 39.161 16.296 ;
     RECT  38.873 7.92 40.208 12.84 ;
     RECT  39.161 15.792 40.208 15.816 ;
     RECT  37.804 17.616 40.208 19.032 ;
     RECT  38.195 23.952 40.208 25.176 ;
     RECT  38.195 26.592 40.208 26.616 ;
     RECT  40.208 2.148 40.312 27.552 ;
     RECT  40.312 2.418 40.4 27.552 ;
     RECT  40.4 2.418 40.504 27.822 ;
     RECT  40.504 24.192 41.941 25.272 ;
     RECT  40.504 17.616 42.421 19.032 ;
     RECT  40.504 7.92 42.908 12.84 ;
     RECT  40.504 15.792 42.908 15.816 ;
     RECT  42.421 17.616 42.908 19.656 ;
     RECT  41.941 23.904 42.908 25.272 ;
     RECT  40.504 26.592 42.908 26.616 ;
     RECT  42.908 2.148 43.012 27.552 ;
     RECT  43.012 2.418 43.1 27.552 ;
     RECT  43.1 2.418 43.204 27.822 ;
     RECT  43.204 7.92 45.608 12.84 ;
     RECT  43.204 15.792 45.608 15.816 ;
     RECT  43.204 17.616 45.608 19.656 ;
     RECT  43.204 23.904 45.608 24.168 ;
     RECT  43.204 26.592 45.608 26.616 ;
     RECT  45.608 2.148 45.712 27.552 ;
     RECT  45.712 2.418 45.8 27.552 ;
     RECT  45.8 2.418 45.904 27.822 ;
     RECT  45.904 15.696 46.793 15.816 ;
     RECT  45.904 7.92 48.308 12.84 ;
     RECT  46.793 15.792 48.308 15.816 ;
     RECT  45.904 17.616 48.308 19.656 ;
     RECT  45.904 23.808 48.308 24.168 ;
     RECT  45.904 26.592 48.308 26.616 ;
     RECT  48.308 2.148 48.412 27.552 ;
     RECT  48.412 2.418 48.5 27.552 ;
     RECT  48.5 2.418 48.604 27.822 ;
     RECT  48.604 7.92 51.008 12.84 ;
     RECT  48.604 15.792 51.008 15.816 ;
     RECT  48.604 17.616 51.008 19.656 ;
     RECT  51.008 2.148 51.112 27.552 ;
     RECT  51.112 2.418 51.2 27.552 ;
     RECT  51.2 2.418 51.304 27.822 ;
     RECT  51.304 7.92 53.708 12.84 ;
     RECT  51.304 15.792 53.708 15.816 ;
     RECT  51.304 17.616 53.708 19.656 ;
     RECT  53.708 2.148 53.812 27.552 ;
     RECT  53.812 2.418 53.9 27.552 ;
     RECT  53.9 2.418 54.004 27.822 ;
     RECT  54.004 15.696 54.749 15.816 ;
     RECT  54.004 7.92 56.408 12.84 ;
     RECT  54.749 15.792 56.408 15.816 ;
     RECT  54.004 17.616 56.408 19.656 ;
     RECT  56.408 2.148 56.512 27.552 ;
     RECT  56.512 2.418 56.6 27.552 ;
     RECT  56.6 2.418 56.704 27.822 ;
     RECT  56.704 7.92 58.093 12.84 ;
     RECT  56.704 14.112 58.093 14.136 ;
     RECT  58.093 7.92 59.108 14.136 ;
     RECT  56.704 15.792 59.108 16.584 ;
     RECT  56.704 17.616 59.108 19.656 ;
     RECT  59.108 2.148 59.212 27.552 ;
     RECT  59.212 2.418 59.3 27.552 ;
     RECT  59.3 2.418 59.404 27.822 ;
     RECT  59.404 15.792 60.113 19.656 ;
     RECT  59.404 7.92 60.937 14.136 ;
     RECT  60.113 15.792 60.937 19.032 ;
     RECT  60.937 7.92 61.808 19.032 ;
     RECT  61.808 2.148 61.912 27.552 ;
     RECT  61.912 2.418 62 27.552 ;
     RECT  62 2.418 62.104 27.822 ;
     RECT  62.104 6.96 63.313 19.08 ;
     RECT  63.313 6.96 63.853 19.176 ;
     RECT  63.853 6.864 64.692 6.888 ;
     RECT  63.853 6.888 64.716 6.96 ;
     RECT  63.853 6.96 64.692 6.984 ;
     RECT  63.853 6.984 64.716 7.056 ;
     RECT  63.853 7.056 64.692 7.08 ;
     RECT  63.853 7.08 64.716 7.152 ;
     RECT  63.853 7.152 64.692 7.176 ;
     RECT  63.853 7.176 64.716 7.248 ;
     RECT  63.853 7.248 64.692 7.272 ;
     RECT  63.853 7.272 64.716 7.344 ;
     RECT  63.853 7.344 64.692 7.368 ;
     RECT  63.853 7.368 64.716 7.44 ;
     RECT  63.853 7.44 64.692 7.464 ;
     RECT  63.853 7.464 64.716 7.536 ;
     RECT  63.853 7.536 64.692 7.56 ;
     RECT  63.853 7.56 64.716 7.632 ;
     RECT  63.853 7.632 64.692 7.656 ;
     RECT  63.853 7.656 64.716 7.728 ;
     RECT  63.853 7.728 64.692 7.752 ;
     RECT  63.853 7.752 64.716 7.824 ;
     RECT  63.853 7.824 64.692 7.848 ;
     RECT  63.853 7.848 64.716 7.92 ;
     RECT  63.853 7.92 64.692 7.944 ;
     RECT  63.853 7.944 64.716 8.016 ;
     RECT  63.853 8.016 64.692 8.04 ;
     RECT  63.853 8.04 64.716 8.112 ;
     RECT  63.853 8.112 64.692 8.136 ;
     RECT  63.853 8.136 64.716 8.208 ;
     RECT  63.853 8.208 64.692 8.232 ;
     RECT  63.853 8.232 64.716 8.304 ;
     RECT  63.853 8.304 64.692 8.328 ;
     RECT  63.853 8.328 64.716 8.4 ;
     RECT  63.853 8.4 64.692 8.424 ;
     RECT  63.853 8.424 64.716 8.496 ;
     RECT  63.853 8.496 64.692 8.52 ;
     RECT  63.853 8.52 64.716 8.592 ;
     RECT  63.853 8.592 64.692 8.616 ;
     RECT  63.853 8.616 64.716 8.688 ;
     RECT  63.853 8.688 64.692 8.712 ;
     RECT  63.853 8.712 64.716 8.784 ;
     RECT  63.853 8.784 64.692 8.808 ;
     RECT  63.853 8.808 64.716 8.88 ;
     RECT  63.853 8.88 64.692 8.904 ;
     RECT  63.853 8.904 64.716 8.976 ;
     RECT  63.853 8.976 64.692 9 ;
     RECT  63.853 9 64.716 9.072 ;
     RECT  63.853 9.072 64.692 9.096 ;
     RECT  63.853 9.096 64.716 9.168 ;
     RECT  63.853 9.168 64.692 9.192 ;
     RECT  63.853 9.192 64.716 9.264 ;
     RECT  63.853 9.264 64.692 9.288 ;
     RECT  63.853 9.288 64.716 9.36 ;
     RECT  63.853 9.36 64.692 9.384 ;
     RECT  63.853 9.384 64.716 9.456 ;
     RECT  63.853 9.456 64.692 9.48 ;
     RECT  63.853 9.48 64.716 9.552 ;
     RECT  63.853 9.552 64.692 9.576 ;
     RECT  63.853 9.576 64.716 9.648 ;
     RECT  63.853 9.648 64.692 9.672 ;
     RECT  63.853 9.672 64.716 9.744 ;
     RECT  63.853 9.744 64.692 9.768 ;
     RECT  63.853 9.768 64.716 9.84 ;
     RECT  63.853 9.84 64.692 9.864 ;
     RECT  63.853 9.864 64.716 9.936 ;
     RECT  63.853 9.936 64.692 9.96 ;
     RECT  63.853 9.96 64.716 10.032 ;
     RECT  63.853 10.032 64.692 10.056 ;
     RECT  63.853 10.056 64.716 10.128 ;
     RECT  63.853 10.128 64.692 10.152 ;
     RECT  63.853 10.152 64.716 10.224 ;
     RECT  63.853 10.224 64.692 10.248 ;
     RECT  63.853 10.248 64.716 10.32 ;
     RECT  63.853 10.32 64.692 10.344 ;
     RECT  63.853 10.344 64.716 10.416 ;
     RECT  63.853 10.416 64.692 10.44 ;
     RECT  63.853 10.44 64.716 10.512 ;
     RECT  63.853 10.512 64.692 10.536 ;
     RECT  63.853 10.536 64.716 10.608 ;
     RECT  63.853 10.608 64.692 10.632 ;
     RECT  63.853 10.632 64.716 10.704 ;
     RECT  63.853 10.704 64.692 10.728 ;
     RECT  63.853 10.728 64.716 10.8 ;
     RECT  63.853 10.8 64.692 10.824 ;
     RECT  63.853 10.824 64.716 10.896 ;
     RECT  63.853 10.896 64.692 10.92 ;
     RECT  63.853 10.92 64.716 10.992 ;
     RECT  63.853 10.992 64.692 11.016 ;
     RECT  63.853 11.016 64.716 11.088 ;
     RECT  63.853 11.088 64.692 11.112 ;
     RECT  63.853 11.112 64.716 11.184 ;
     RECT  63.853 11.184 64.692 11.208 ;
     RECT  63.853 11.208 64.716 11.28 ;
     RECT  63.853 11.28 64.692 11.304 ;
     RECT  63.853 11.304 64.716 11.376 ;
     RECT  63.853 11.376 64.692 11.4 ;
     RECT  63.853 11.4 64.716 11.472 ;
     RECT  63.853 11.472 64.692 11.496 ;
     RECT  63.853 11.496 64.716 11.568 ;
     RECT  63.853 11.568 64.692 11.592 ;
     RECT  63.853 11.592 64.716 11.664 ;
     RECT  63.853 11.664 64.692 11.688 ;
     RECT  63.853 11.688 64.716 11.76 ;
     RECT  63.853 11.76 64.692 11.784 ;
     RECT  63.853 11.784 64.716 11.856 ;
     RECT  63.853 11.856 64.692 11.88 ;
     RECT  63.853 11.88 64.716 11.952 ;
     RECT  63.853 11.952 64.692 11.976 ;
     RECT  63.853 11.976 64.716 12.048 ;
     RECT  63.853 12.048 64.692 12.072 ;
     RECT  63.853 12.072 64.716 12.144 ;
     RECT  63.853 12.144 64.692 12.168 ;
     RECT  63.853 12.168 64.716 12.24 ;
     RECT  63.853 12.24 64.692 12.264 ;
     RECT  63.853 12.264 64.716 12.336 ;
     RECT  63.853 12.336 64.692 12.36 ;
     RECT  63.853 12.36 64.716 12.432 ;
     RECT  63.853 12.432 64.692 12.456 ;
     RECT  63.853 12.456 64.716 12.528 ;
     RECT  63.853 12.528 64.692 12.552 ;
     RECT  63.853 12.552 64.716 12.624 ;
     RECT  63.853 12.624 64.692 12.648 ;
     RECT  63.853 12.648 64.716 12.72 ;
     RECT  63.853 12.72 64.692 12.744 ;
     RECT  63.853 12.744 64.716 12.816 ;
     RECT  63.853 12.816 64.692 12.84 ;
     RECT  63.853 12.84 64.716 12.912 ;
     RECT  63.853 12.912 64.692 12.936 ;
     RECT  63.853 12.936 64.716 13.008 ;
     RECT  63.853 13.008 64.692 13.032 ;
     RECT  63.853 13.032 64.716 13.104 ;
     RECT  63.853 13.104 64.692 13.128 ;
     RECT  63.853 13.128 64.716 13.2 ;
     RECT  63.853 13.2 64.692 13.224 ;
     RECT  63.853 13.224 64.716 13.296 ;
     RECT  63.853 13.296 64.692 13.32 ;
     RECT  63.853 13.32 64.716 13.392 ;
     RECT  63.853 13.392 64.692 13.416 ;
     RECT  63.853 13.416 64.716 13.488 ;
     RECT  63.853 13.488 64.692 13.512 ;
     RECT  63.853 13.512 64.716 13.584 ;
     RECT  63.853 13.584 64.692 13.608 ;
     RECT  63.853 13.608 64.716 13.68 ;
     RECT  63.853 13.68 64.692 13.704 ;
     RECT  63.853 13.704 64.716 13.776 ;
     RECT  63.853 13.776 64.692 13.8 ;
     RECT  63.853 13.8 64.716 13.872 ;
     RECT  63.853 13.872 64.692 13.896 ;
     RECT  63.853 13.896 64.716 13.968 ;
     RECT  63.853 13.968 64.692 13.992 ;
     RECT  63.853 13.992 64.716 14.064 ;
     RECT  63.853 14.064 64.692 14.088 ;
     RECT  63.853 14.088 64.716 14.16 ;
     RECT  63.853 14.16 64.692 14.184 ;
     RECT  63.853 14.184 64.716 14.256 ;
     RECT  63.853 14.256 64.692 14.28 ;
     RECT  63.853 14.28 64.716 14.352 ;
     RECT  63.853 14.352 64.692 14.376 ;
     RECT  63.853 14.376 64.716 14.448 ;
     RECT  63.853 14.448 64.692 14.472 ;
     RECT  63.853 14.472 64.716 14.544 ;
     RECT  63.853 14.544 64.692 14.568 ;
     RECT  63.853 14.568 64.716 14.64 ;
     RECT  63.853 14.64 64.692 14.664 ;
     RECT  63.853 14.664 64.716 14.736 ;
     RECT  63.853 14.736 64.692 14.76 ;
     RECT  63.853 14.76 64.716 14.832 ;
     RECT  63.853 14.832 64.692 14.856 ;
     RECT  63.853 14.856 64.716 14.928 ;
     RECT  63.853 14.928 64.692 14.952 ;
     RECT  63.853 14.952 64.716 15.024 ;
     RECT  63.853 15.024 64.692 15.048 ;
     RECT  63.853 15.048 64.716 15.12 ;
     RECT  63.853 15.12 64.692 15.144 ;
     RECT  63.853 15.144 64.716 15.216 ;
     RECT  63.853 15.216 64.692 15.24 ;
     RECT  63.853 15.24 64.716 15.312 ;
     RECT  63.853 15.312 64.692 15.336 ;
     RECT  63.853 15.336 64.716 15.408 ;
     RECT  63.853 15.408 64.692 15.432 ;
     RECT  63.853 15.432 64.716 15.504 ;
     RECT  63.853 15.504 64.692 15.528 ;
     RECT  63.853 15.528 64.716 15.6 ;
     RECT  63.853 15.6 64.692 15.624 ;
     RECT  63.853 15.624 64.716 15.696 ;
     RECT  63.853 15.696 64.692 15.72 ;
     RECT  63.853 15.72 64.716 15.792 ;
     RECT  63.853 15.792 64.692 15.816 ;
     RECT  63.853 15.816 64.716 15.888 ;
     RECT  63.853 15.888 64.692 15.912 ;
     RECT  63.853 15.912 64.716 15.984 ;
     RECT  63.853 15.984 64.692 16.008 ;
     RECT  63.853 16.008 64.716 16.08 ;
     RECT  63.853 16.08 64.692 16.104 ;
     RECT  63.853 16.104 64.716 16.176 ;
     RECT  63.853 16.176 64.692 16.2 ;
     RECT  63.853 16.2 64.716 16.272 ;
     RECT  63.853 16.272 64.692 16.296 ;
     RECT  63.853 16.296 64.716 16.368 ;
     RECT  63.853 16.368 64.692 16.392 ;
     RECT  63.853 16.392 64.716 16.464 ;
     RECT  63.853 16.464 64.692 16.488 ;
     RECT  63.853 16.488 64.716 16.56 ;
     RECT  63.853 16.56 64.692 16.584 ;
     RECT  63.853 16.584 64.716 16.656 ;
     RECT  63.853 16.656 64.692 16.68 ;
     RECT  63.853 16.68 64.716 16.752 ;
     RECT  63.853 16.752 64.692 16.776 ;
     RECT  63.853 16.776 64.716 16.848 ;
     RECT  63.853 16.848 64.692 16.872 ;
     RECT  63.853 16.872 64.716 16.944 ;
     RECT  63.853 16.944 64.692 16.968 ;
     RECT  63.853 16.968 64.716 17.04 ;
     RECT  63.853 17.04 64.692 17.064 ;
     RECT  63.853 17.064 64.716 17.136 ;
     RECT  63.853 17.136 64.692 17.16 ;
     RECT  63.853 17.16 64.716 17.232 ;
     RECT  63.853 17.232 64.692 17.256 ;
     RECT  63.853 17.256 64.716 17.328 ;
     RECT  63.853 17.328 64.692 17.352 ;
     RECT  63.853 17.352 64.716 17.424 ;
     RECT  63.853 17.424 64.692 17.448 ;
     RECT  63.853 17.448 64.716 17.52 ;
     RECT  63.853 17.52 64.692 17.544 ;
     RECT  63.853 17.544 64.716 17.616 ;
     RECT  63.853 17.616 64.692 17.64 ;
     RECT  63.853 17.64 64.716 17.712 ;
     RECT  63.853 17.712 64.692 17.736 ;
     RECT  63.853 17.736 64.716 17.808 ;
     RECT  63.853 17.808 64.692 17.832 ;
     RECT  63.853 17.832 64.716 17.904 ;
     RECT  63.853 17.904 64.692 17.928 ;
     RECT  63.853 17.928 64.716 18 ;
     RECT  63.853 18 64.692 18.024 ;
     RECT  63.853 18.024 64.716 18.096 ;
     RECT  63.853 18.096 64.692 18.12 ;
     RECT  63.853 18.12 64.716 18.192 ;
     RECT  63.853 18.192 64.692 18.216 ;
     RECT  63.853 18.216 64.716 18.288 ;
     RECT  63.853 18.288 64.692 18.312 ;
     RECT  63.853 18.312 64.716 18.384 ;
     RECT  63.853 18.384 64.692 18.408 ;
     RECT  63.853 18.408 64.716 18.48 ;
     RECT  63.853 18.48 64.692 18.504 ;
     RECT  63.853 18.504 64.716 18.576 ;
     RECT  63.853 18.576 64.692 18.6 ;
     RECT  63.853 18.6 64.716 18.672 ;
     RECT  63.853 18.672 64.692 18.696 ;
     RECT  63.853 18.696 64.716 18.768 ;
     RECT  63.853 18.768 64.692 18.792 ;
     RECT  63.853 18.792 64.716 18.864 ;
     RECT  63.853 18.864 64.692 18.888 ;
     RECT  63.853 18.888 64.716 18.96 ;
     RECT  63.853 18.96 64.692 18.984 ;
     RECT  63.853 18.984 64.716 19.056 ;
     RECT  63.853 19.056 64.692 19.08 ;
     RECT  63.853 19.08 64.716 19.152 ;
     RECT  63.853 19.152 64.692 19.176 ;
     RECT  64.716 9.504 64.757 9.528 ;
     RECT  64.716 11.808 64.757 11.856 ;
     RECT  64.716 11.88 64.757 11.952 ;
     RECT  64.716 11.976 64.757 12.048 ;
     RECT  64.716 12.072 64.757 12.144 ;
     RECT  64.716 12.168 64.757 12.24 ;
     RECT  64.716 12.264 64.757 12.336 ;
     RECT  64.716 12.36 64.757 12.432 ;
     RECT  64.716 12.456 64.757 12.528 ;
     RECT  64.716 12.552 64.757 12.624 ;
     RECT  64.716 12.648 64.757 12.72 ;
     RECT  64.716 12.744 64.757 12.792 ;
     RECT  64.716 14.112 64.757 14.136 ;
     RECT  64.716 17.76 64.757 17.808 ;
     RECT  64.716 17.832 64.757 17.904 ;
     RECT  64.716 17.928 64.757 18 ;
     RECT  64.716 18.024 64.757 18.096 ;
     RECT  64.716 18.12 64.757 18.168 ;
    LAYER M5 ;
     RECT  2.4 2.137 2.52 2.151 ;
     RECT  5.1 2.137 5.22 2.151 ;
     RECT  7.8 2.137 7.92 2.151 ;
     RECT  10.5 2.137 10.62 2.151 ;
     RECT  13.2 2.137 13.32 2.151 ;
     RECT  15.9 2.137 16.02 2.151 ;
     RECT  18.6 2.137 18.72 2.151 ;
     RECT  21.3 2.137 21.42 2.151 ;
     RECT  24 2.137 24.12 2.151 ;
     RECT  26.7 2.137 26.82 2.151 ;
     RECT  29.4 2.137 29.52 2.151 ;
     RECT  32.1 2.137 32.22 2.151 ;
     RECT  34.8 2.137 34.92 2.151 ;
     RECT  37.5 2.137 37.62 2.151 ;
     RECT  40.2 2.137 40.32 2.151 ;
     RECT  42.9 2.137 43.02 2.151 ;
     RECT  45.6 2.137 45.72 2.151 ;
     RECT  48.3 2.137 48.42 2.151 ;
     RECT  51 2.137 51.12 2.151 ;
     RECT  53.7 2.137 53.82 2.151 ;
     RECT  56.4 2.137 56.52 2.151 ;
     RECT  59.1 2.137 59.22 2.151 ;
     RECT  61.8 2.137 61.92 2.151 ;
     RECT  32.1 2.151 32.412 8.965 ;
     RECT  31.968 8.965 32.412 10.069 ;
     RECT  2.4 2.151 2.712 14.101 ;
     RECT  2.304 14.101 2.712 14.725 ;
     RECT  2.304 14.725 2.856 14.773 ;
     RECT  2.304 14.773 3.432 15.349 ;
     RECT  5.1 2.151 5.412 15.349 ;
     RECT  2.304 15.349 5.412 15.491 ;
     RECT  2.304 15.491 2.952 15.779 ;
     RECT  2.4 15.779 2.952 16.019 ;
     RECT  42.9 2.151 43.212 19.621 ;
     RECT  26.7 2.151 27.012 20.293 ;
     RECT  31.92 10.069 32.412 20.725 ;
     RECT  26.7 20.293 27.144 20.869 ;
     RECT  26.112 20.869 27.144 21.251 ;
     RECT  29.4 2.151 29.712 21.925 ;
     RECT  4.272 15.491 5.412 21.971 ;
     RECT  34.8 2.151 35.112 22.165 ;
     RECT  31.728 20.725 32.412 22.213 ;
     RECT  31.728 22.213 32.616 22.261 ;
     RECT  31.728 22.261 32.712 22.453 ;
     RECT  29.28 21.925 29.712 22.645 ;
     RECT  33.984 22.165 35.112 22.741 ;
     RECT  2.4 16.019 2.856 22.835 ;
     RECT  26.112 21.251 27.012 23.317 ;
     RECT  31.344 22.453 32.712 23.365 ;
     RECT  30.96 23.365 32.712 23.701 ;
     RECT  33.84 22.741 35.112 23.701 ;
     RECT  30.96 23.701 35.208 23.845 ;
     RECT  26.112 23.317 27.336 23.893 ;
     RECT  29.28 22.645 29.832 23.893 ;
     RECT  30.96 23.845 35.976 23.893 ;
     RECT  42.432 19.621 43.212 23.893 ;
     RECT  26.112 23.893 27.96 24.325 ;
     RECT  29.28 23.893 35.976 24.325 ;
     RECT  37.5 2.151 37.812 24.469 ;
     RECT  37.392 24.469 37.812 24.613 ;
     RECT  26.112 24.325 35.976 24.755 ;
     RECT  41.952 23.893 43.212 24.899 ;
     RECT  37.392 24.613 37.944 24.901 ;
     RECT  37.392 24.901 38.184 25.187 ;
     RECT  42.432 24.899 43.212 25.283 ;
     RECT  26.7 24.755 35.976 25.715 ;
     RECT  37.5 25.187 38.184 25.763 ;
     RECT  29.184 25.715 35.976 26.243 ;
     RECT  29.184 26.243 35.592 27.347 ;
     RECT  2.4 22.835 2.712 27.819 ;
     RECT  5.1 21.971 5.412 27.819 ;
     RECT  7.8 2.151 8.112 27.819 ;
     RECT  10.5 2.151 10.812 27.819 ;
     RECT  13.2 2.151 13.512 27.819 ;
     RECT  15.9 2.151 16.212 27.819 ;
     RECT  18.6 2.151 18.912 27.819 ;
     RECT  21.3 2.151 21.612 27.819 ;
     RECT  24 2.151 24.312 27.819 ;
     RECT  26.7 25.715 27.012 27.819 ;
     RECT  29.4 27.347 35.592 27.819 ;
     RECT  37.5 25.763 37.812 27.819 ;
     RECT  40.2 2.151 40.512 27.819 ;
     RECT  42.9 25.283 43.212 27.819 ;
     RECT  45.6 2.151 45.912 27.819 ;
     RECT  48.3 2.151 48.612 27.819 ;
     RECT  51 2.151 51.312 27.819 ;
     RECT  53.7 2.151 54.012 27.819 ;
     RECT  56.4 2.151 56.712 27.819 ;
     RECT  59.1 2.151 59.412 27.819 ;
     RECT  61.8 2.151 62.112 27.819 ;
     RECT  2.592 27.819 2.712 27.833 ;
     RECT  5.292 27.819 5.412 27.833 ;
     RECT  7.992 27.819 8.112 27.833 ;
     RECT  10.692 27.819 10.812 27.833 ;
     RECT  13.392 27.819 13.512 27.833 ;
     RECT  16.092 27.819 16.212 27.833 ;
     RECT  18.792 27.819 18.912 27.833 ;
     RECT  21.492 27.819 21.612 27.833 ;
     RECT  24.192 27.819 24.312 27.833 ;
     RECT  26.892 27.819 27.012 27.833 ;
     RECT  29.592 27.819 35.592 27.833 ;
     RECT  37.692 27.819 37.812 27.833 ;
     RECT  40.392 27.819 40.512 27.833 ;
     RECT  43.092 27.819 43.212 27.833 ;
     RECT  45.792 27.819 45.912 27.833 ;
     RECT  48.492 27.819 48.612 27.833 ;
     RECT  51.192 27.819 51.312 27.833 ;
     RECT  53.892 27.819 54.012 27.833 ;
     RECT  56.592 27.819 56.712 27.833 ;
     RECT  59.292 27.819 59.412 27.833 ;
     RECT  61.992 27.819 62.112 27.833 ;
     RECT  29.808 27.833 35.592 29.749 ;
     RECT  29.52 29.749 35.592 30.132 ;
     RECT  29.544 30.132 29.616 30.16 ;
     RECT  29.64 30.132 29.712 30.16 ;
     RECT  29.736 30.132 29.808 30.16 ;
     RECT  29.832 30.132 29.904 30.16 ;
     RECT  29.928 30.132 30 30.16 ;
     RECT  30.024 30.132 30.096 30.16 ;
     RECT  30.12 30.132 30.192 30.16 ;
     RECT  30.216 30.132 30.288 30.16 ;
     RECT  30.312 30.132 30.384 30.16 ;
     RECT  30.408 30.132 30.48 30.16 ;
     RECT  30.504 30.132 30.576 30.16 ;
     RECT  30.6 30.132 30.672 30.16 ;
     RECT  30.696 30.132 30.768 30.16 ;
     RECT  30.792 30.132 30.864 30.16 ;
     RECT  30.888 30.132 30.96 30.16 ;
     RECT  30.984 30.132 31.056 30.16 ;
     RECT  31.08 30.132 31.152 30.16 ;
     RECT  31.176 30.132 31.248 30.16 ;
     RECT  31.272 30.132 31.344 30.16 ;
     RECT  31.368 30.132 31.44 30.16 ;
     RECT  31.464 30.132 31.536 30.16 ;
     RECT  31.56 30.132 31.632 30.16 ;
     RECT  31.656 30.132 31.728 30.16 ;
     RECT  31.752 30.132 31.824 30.16 ;
     RECT  31.848 30.132 31.92 30.16 ;
     RECT  31.944 30.132 32.016 30.16 ;
     RECT  32.04 30.132 32.112 30.16 ;
     RECT  32.136 30.132 32.208 30.16 ;
     RECT  32.232 30.132 32.304 30.16 ;
     RECT  32.328 30.132 32.4 30.16 ;
     RECT  32.424 30.132 32.496 30.16 ;
     RECT  32.52 30.132 32.592 30.16 ;
     RECT  32.616 30.132 32.688 30.16 ;
     RECT  32.712 30.132 32.784 30.16 ;
     RECT  32.808 30.132 32.88 30.16 ;
     RECT  32.904 30.132 32.976 30.16 ;
     RECT  33 30.132 33.072 30.16 ;
     RECT  33.096 30.132 33.168 30.16 ;
     RECT  33.192 30.132 33.264 30.16 ;
     RECT  33.288 30.132 33.36 30.16 ;
     RECT  33.384 30.132 33.456 30.16 ;
     RECT  33.48 30.132 33.552 30.16 ;
     RECT  33.576 30.132 33.648 30.16 ;
     RECT  33.672 30.132 33.744 30.16 ;
     RECT  33.768 30.132 33.84 30.16 ;
     RECT  33.864 30.132 33.936 30.16 ;
     RECT  33.96 30.132 34.032 30.16 ;
     RECT  34.056 30.132 34.128 30.16 ;
     RECT  34.152 30.132 34.224 30.16 ;
     RECT  34.248 30.132 34.32 30.16 ;
     RECT  34.344 30.132 34.416 30.16 ;
     RECT  34.44 30.132 34.512 30.16 ;
     RECT  34.536 30.132 34.608 30.16 ;
     RECT  34.632 30.132 34.704 30.16 ;
     RECT  34.728 30.132 34.8 30.16 ;
     RECT  34.824 30.132 34.896 30.16 ;
     RECT  34.92 30.132 34.992 30.16 ;
     RECT  35.016 30.132 35.088 30.16 ;
     RECT  35.112 30.132 35.184 30.16 ;
     RECT  35.208 30.132 35.28 30.16 ;
     RECT  35.304 30.132 35.376 30.16 ;
     RECT  35.4 30.132 35.472 30.16 ;
     RECT  35.496 30.132 35.568 30.16 ;
     RECT  2.952 15.491 4.272 16.019 ;
     RECT  2.856 16.019 4.272 21.971 ;
     RECT  32.616 22.213 33.984 22.261 ;
     RECT  32.712 22.261 33.984 22.741 ;
     RECT  29.832 22.645 31.344 23.365 ;
     RECT  32.712 22.741 33.84 23.701 ;
     RECT  29.832 23.365 30.96 23.893 ;
     RECT  35.976 23.845 37.5 24.469 ;
     RECT  27.96 23.893 29.28 24.325 ;
     RECT  40.512 23.893 41.952 24.899 ;
     RECT  35.976 24.469 37.392 25.187 ;
     RECT  35.976 25.187 37.5 26.243 ;
  END
END qfd_rlyh0_128_NE_65x30
END LIBRARY
